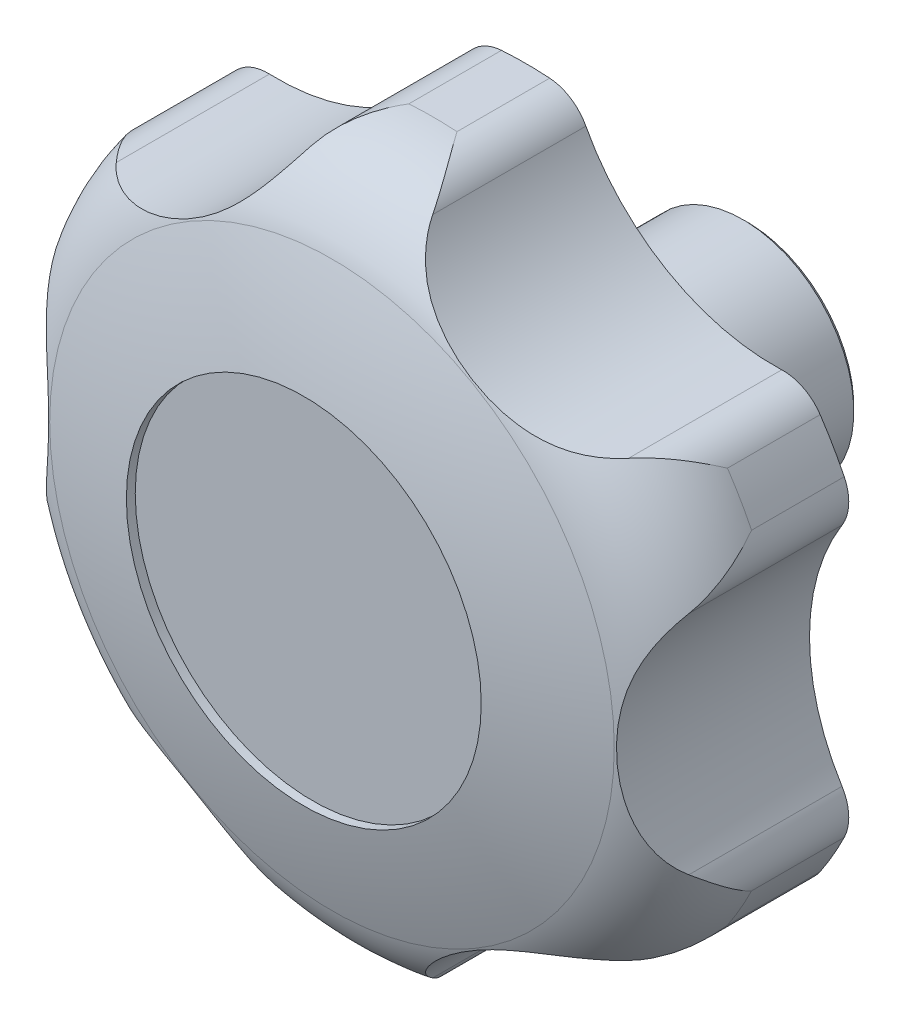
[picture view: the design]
ISO-10303-21;
HEADER;
FILE_DESCRIPTION(('STEP AP214'),'2;1');
FILE_NAME('part.step','',(''),(''),'','','');
FILE_SCHEMA(('AUTOMOTIVE_DESIGN { 1 0 10303 214 1 1 1 1 }'));
ENDSEC;
DATA;
#1=APPLICATION_CONTEXT('core data for automotive mechanical design processes');
#2=APPLICATION_PROTOCOL_DEFINITION('international standard','automotive_design',2000,#1);
#3=PRODUCT_CONTEXT('',#1,'mechanical');
#4=PRODUCT('Part','Part','',(#3));
#5=PRODUCT_RELATED_PRODUCT_CATEGORY('part','',(#4));
#6=PRODUCT_DEFINITION_FORMATION('','',#4);
#7=PRODUCT_DEFINITION_CONTEXT('part definition',#1,'design');
#8=PRODUCT_DEFINITION('design','',#6,#7);
#9=PRODUCT_DEFINITION_SHAPE('','',#8);
#10=(LENGTH_UNIT() NAMED_UNIT(*) SI_UNIT(.MILLI.,.METRE.));
#11=(NAMED_UNIT(*) PLANE_ANGLE_UNIT() SI_UNIT($,.RADIAN.));
#12=(NAMED_UNIT(*) SI_UNIT($,.STERADIAN.) SOLID_ANGLE_UNIT());
#13=UNCERTAINTY_MEASURE_WITH_UNIT(LENGTH_MEASURE(1.E-05),#10,'distance_accuracy_value','');
#14=(GEOMETRIC_REPRESENTATION_CONTEXT(3) GLOBAL_UNCERTAINTY_ASSIGNED_CONTEXT((#13)) GLOBAL_UNIT_ASSIGNED_CONTEXT((#10,
#11,#12)) REPRESENTATION_CONTEXT('',''));
#15=CARTESIAN_POINT('',(0.,0.,0.));
#16=DIRECTION('',(0.,0.,1.));
#17=DIRECTION('',(1.,0.,0.));
#18=AXIS2_PLACEMENT_3D('',#15,#16,#17);
#19=CARTESIAN_POINT('',(0.,0.,64.59576815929));
#20=DIRECTION('',(0.,0.,1.));
#21=DIRECTION('',(-1.,0.,0.));
#22=AXIS2_PLACEMENT_3D('',#19,#20,#21);
#23=CYLINDRICAL_SURFACE('',#22,40.);
#24=CARTESIAN_POINT('',(0.,0.,25.));
#25=DIRECTION('',(0.,0.,1.));
#26=DIRECTION('',(-1.,0.,0.));
#27=AXIS2_PLACEMENT_3D('',#24,#25,#26);
#28=CIRCLE('',#27,40.);
#29=CARTESIAN_POINT('',(33.2039586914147,-22.3046436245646,25.));
#30=VERTEX_POINT('',#29);
#31=CARTESIAN_POINT('',(35.9183673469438,-17.603149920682,25.));
#32=VERTEX_POINT('',#31);
#33=EDGE_CURVE('E457',#30,#32,#28,.T.);
#34=ORIENTED_EDGE('',*,*,#33,.T.);
#35=DIRECTION('',(0.,0.,1.));
#36=VECTOR('',#35,1.);
#37=CARTESIAN_POINT('',(35.9183673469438,-17.603149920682,0.));
#38=LINE('',#37,#36);
#39=CARTESIAN_POINT('',(35.9183673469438,-17.603149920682,35.4470247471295));
#40=VERTEX_POINT('',#39);
#41=EDGE_CURVE('E182',#32,#40,#38,.T.);
#42=ORIENTED_EDGE('',*,*,#41,.T.);
#43=CARTESIAN_POINT('',(0.,0.,35.4470247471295));
#44=DIRECTION('',(0.,0.,1.));
#45=DIRECTION('',(-1.,0.,0.));
#46=AXIS2_PLACEMENT_3D('',#43,#44,#45);
#47=CIRCLE('',#46,40.);
#48=CARTESIAN_POINT('',(33.2039586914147,-22.3046436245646,35.4470247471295));
#49=VERTEX_POINT('',#48);
#50=EDGE_CURVE('E198',#49,#40,#47,.T.);
#51=ORIENTED_EDGE('',*,*,#50,.F.);
#52=DIRECTION('',(0.,0.,1.));
#53=VECTOR('',#52,1.);
#54=CARTESIAN_POINT('',(33.2039586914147,-22.3046436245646,0.));
#55=LINE('',#54,#53);
#56=EDGE_CURVE('E526',#30,#49,#55,.T.);
#57=ORIENTED_EDGE('',*,*,#56,.F.);
#58=EDGE_LOOP('',(#34,#42,#51,#57));
#59=FACE_BOUND('',#58,.T.);
#60=ADVANCED_FACE('F14',(#59),#23,.T.);
#61=CARTESIAN_POINT('',(-2.71440865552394,-39.9077935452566,25.));
#62=VERTEX_POINT('',#61);
#63=CARTESIAN_POINT('',(2.71440865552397,-39.9077935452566,25.));
#64=VERTEX_POINT('',#63);
#65=EDGE_CURVE('E460',#62,#64,#28,.T.);
#66=ORIENTED_EDGE('',*,*,#65,.T.);
#67=DIRECTION('',(0.,0.,1.));
#68=VECTOR('',#67,1.);
#69=CARTESIAN_POINT('',(2.71440865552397,-39.9077935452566,0.));
#70=LINE('',#69,#68);
#71=CARTESIAN_POINT('',(2.71440865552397,-39.9077935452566,35.4470247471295));
#72=VERTEX_POINT('',#71);
#73=EDGE_CURVE('E532',#64,#72,#70,.T.);
#74=ORIENTED_EDGE('',*,*,#73,.T.);
#75=CARTESIAN_POINT('',(-2.71440865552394,-39.9077935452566,35.4470247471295));
#76=VERTEX_POINT('',#75);
#77=EDGE_CURVE('E474',#76,#72,#47,.T.);
#78=ORIENTED_EDGE('',*,*,#77,.F.);
#79=DIRECTION('',(0.,0.,1.));
#80=VECTOR('',#79,1.);
#81=CARTESIAN_POINT('',(-2.71440865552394,-39.9077935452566,0.));
#82=LINE('',#81,#80);
#83=EDGE_CURVE('E535',#62,#76,#82,.T.);
#84=ORIENTED_EDGE('',*,*,#83,.F.);
#85=EDGE_LOOP('',(#66,#74,#78,#84));
#86=FACE_BOUND('',#85,.T.);
#87=ADVANCED_FACE('F423',(#86),#23,.T.);
#88=CARTESIAN_POINT('',(-35.9183673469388,-17.603149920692,25.));
#89=VERTEX_POINT('',#88);
#90=CARTESIAN_POINT('',(-33.2039586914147,-22.3046436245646,25.));
#91=VERTEX_POINT('',#90);
#92=EDGE_CURVE('E463',#89,#91,#28,.T.);
#93=ORIENTED_EDGE('',*,*,#92,.T.);
#94=DIRECTION('',(0.,0.,1.));
#95=VECTOR('',#94,1.);
#96=CARTESIAN_POINT('',(-33.2039586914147,-22.3046436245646,0.));
#97=LINE('',#96,#95);
#98=CARTESIAN_POINT('',(-33.2039586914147,-22.3046436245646,35.4470247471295));
#99=VERTEX_POINT('',#98);
#100=EDGE_CURVE('E543',#91,#99,#97,.T.);
#101=ORIENTED_EDGE('',*,*,#100,.T.);
#102=CARTESIAN_POINT('',(-35.9183673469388,-17.603149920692,35.4470247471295));
#103=VERTEX_POINT('',#102);
#104=EDGE_CURVE('E470',#103,#99,#47,.T.);
#105=ORIENTED_EDGE('',*,*,#104,.F.);
#106=DIRECTION('',(0.,0.,1.));
#107=VECTOR('',#106,1.);
#108=CARTESIAN_POINT('',(-35.9183673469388,-17.603149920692,0.));
#109=LINE('',#108,#107);
#110=EDGE_CURVE('E546',#89,#103,#109,.T.);
#111=ORIENTED_EDGE('',*,*,#110,.F.);
#112=EDGE_LOOP('',(#93,#101,#105,#111));
#113=FACE_BOUND('',#112,.T.);
#114=ADVANCED_FACE('F431',(#113),#23,.T.);
#115=CARTESIAN_POINT('',(-33.2039586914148,22.3046436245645,25.));
#116=VERTEX_POINT('',#115);
#117=CARTESIAN_POINT('',(-35.9183673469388,17.603149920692,25.));
#118=VERTEX_POINT('',#117);
#119=EDGE_CURVE('E462',#116,#118,#28,.T.);
#120=ORIENTED_EDGE('',*,*,#119,.T.);
#121=DIRECTION('',(0.,0.,1.));
#122=VECTOR('',#121,1.);
#123=CARTESIAN_POINT('',(-35.9183673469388,17.603149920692,0.));
#124=LINE('',#123,#122);
#125=CARTESIAN_POINT('',(-35.9183673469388,17.603149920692,35.4470247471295));
#126=VERTEX_POINT('',#125);
#127=EDGE_CURVE('E37',#118,#126,#124,.T.);
#128=ORIENTED_EDGE('',*,*,#127,.T.);
#129=CARTESIAN_POINT('',(-33.2039586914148,22.3046436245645,35.4470247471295));
#130=VERTEX_POINT('',#129);
#131=EDGE_CURVE('E467',#130,#126,#47,.T.);
#132=ORIENTED_EDGE('',*,*,#131,.F.);
#133=DIRECTION('',(0.,0.,1.));
#134=VECTOR('',#133,1.);
#135=CARTESIAN_POINT('',(-33.2039586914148,22.3046436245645,0.));
#136=LINE('',#135,#134);
#137=EDGE_CURVE('E555',#116,#130,#136,.T.);
#138=ORIENTED_EDGE('',*,*,#137,.F.);
#139=EDGE_LOOP('',(#120,#128,#132,#138));
#140=FACE_BOUND('',#139,.T.);
#141=ADVANCED_FACE('F444',(#140),#23,.T.);
#142=CARTESIAN_POINT('',(2.71440865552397,39.9077935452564,25.));
#143=VERTEX_POINT('',#142);
#144=CARTESIAN_POINT('',(-2.714408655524,39.9077935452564,25.));
#145=VERTEX_POINT('',#144);
#146=EDGE_CURVE('E458',#143,#145,#28,.T.);
#147=ORIENTED_EDGE('',*,*,#146,.T.);
#148=DIRECTION('',(0.,0.,1.));
#149=VECTOR('',#148,1.);
#150=CARTESIAN_POINT('',(-2.714408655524,39.9077935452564,0.));
#151=LINE('',#150,#149);
#152=CARTESIAN_POINT('',(-2.714408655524,39.9077935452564,35.4470247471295));
#153=VERTEX_POINT('',#152);
#154=EDGE_CURVE('E563',#145,#153,#151,.T.);
#155=ORIENTED_EDGE('',*,*,#154,.T.);
#156=CARTESIAN_POINT('',(2.71440865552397,39.9077935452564,35.4470247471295));
#157=VERTEX_POINT('',#156);
#158=EDGE_CURVE('E876',#157,#153,#47,.T.);
#159=ORIENTED_EDGE('',*,*,#158,.F.);
#160=DIRECTION('',(0.,0.,1.));
#161=VECTOR('',#160,1.);
#162=CARTESIAN_POINT('',(2.71440865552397,39.9077935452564,0.));
#163=LINE('',#162,#161);
#164=EDGE_CURVE('E566',#143,#157,#163,.T.);
#165=ORIENTED_EDGE('',*,*,#164,.F.);
#166=EDGE_LOOP('',(#147,#155,#159,#165));
#167=FACE_BOUND('',#166,.T.);
#168=ADVANCED_FACE('F435',(#167),#23,.T.);
#169=CARTESIAN_POINT('',(35.9183673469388,17.603149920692,25.));
#170=VERTEX_POINT('',#169);
#171=CARTESIAN_POINT('',(33.2039586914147,22.3046436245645,25.));
#172=VERTEX_POINT('',#171);
#173=EDGE_CURVE('E450',#170,#172,#28,.T.);
#174=ORIENTED_EDGE('',*,*,#173,.T.);
#175=DIRECTION('',(0.,0.,1.));
#176=VECTOR('',#175,1.);
#177=CARTESIAN_POINT('',(33.2039586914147,22.3046436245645,0.));
#178=LINE('',#177,#176);
#179=CARTESIAN_POINT('',(33.2039586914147,22.3046436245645,35.4470247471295));
#180=VERTEX_POINT('',#179);
#181=EDGE_CURVE('E452',#172,#180,#178,.T.);
#182=ORIENTED_EDGE('',*,*,#181,.T.);
#183=CARTESIAN_POINT('',(35.9183673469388,17.603149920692,35.4470247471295));
#184=VERTEX_POINT('',#183);
#185=EDGE_CURVE('E883',#184,#180,#47,.T.);
#186=ORIENTED_EDGE('',*,*,#185,.F.);
#187=DIRECTION('',(0.,0.,1.));
#188=VECTOR('',#187,1.);
#189=CARTESIAN_POINT('',(35.9183673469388,17.603149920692,0.));
#190=LINE('',#189,#188);
#191=EDGE_CURVE('E454',#170,#184,#190,.T.);
#192=ORIENTED_EDGE('',*,*,#191,.F.);
#193=EDGE_LOOP('',(#174,#182,#186,#192));
#194=FACE_BOUND('',#193,.T.);
#195=ADVANCED_FACE('F425',(#194),#23,.T.);
#196=CARTESIAN_POINT('',(0.,0.,0.));
#197=DIRECTION('',(0.,0.,1.));
#198=DIRECTION('',(-1.,0.,0.));
#199=AXIS2_PLACEMENT_3D('',#196,#197,#198);
#200=CONICAL_SURFACE('',#199,12.,0.785398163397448);
#201=CARTESIAN_POINT('',(0.,0.,0.5));
#202=DIRECTION('',(0.,0.,1.));
#203=DIRECTION('',(-1.,0.,0.));
#204=AXIS2_PLACEMENT_3D('',#201,#202,#203);
#205=CIRCLE('',#204,12.5);
#206=CARTESIAN_POINT('',(-12.5,0.,0.5));
#207=VERTEX_POINT('',#206);
#208=EDGE_CURVE('E856',#207,#207,#205,.T.);
#209=ORIENTED_EDGE('',*,*,#208,.F.);
#210=EDGE_LOOP('',(#209));
#211=FACE_BOUND('',#210,.T.);
#212=CARTESIAN_POINT('',(0.,0.,0.));
#213=DIRECTION('',(0.,0.,1.));
#214=DIRECTION('',(-1.,0.,0.));
#215=AXIS2_PLACEMENT_3D('',#212,#213,#214);
#216=CIRCLE('',#215,12.);
#217=CARTESIAN_POINT('',(-12.,0.,0.));
#218=VERTEX_POINT('',#217);
#219=EDGE_CURVE('E477',#218,#218,#216,.T.);
#220=ORIENTED_EDGE('',*,*,#219,.T.);
#221=EDGE_LOOP('',(#220));
#222=FACE_BOUND('',#221,.T.);
#223=ADVANCED_FACE('F16',(#211,#222),#200,.T.);
#224=CARTESIAN_POINT('',(0.,-1.94289029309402E-13,0.));
#225=DIRECTION('',(0.,0.,1.));
#226=DIRECTION('',(-1.,0.,0.));
#227=AXIS2_PLACEMENT_3D('',#224,#225,#226);
#228=PLANE('',#227);
#229=CARTESIAN_POINT('',(0.,0.,0.));
#230=DIRECTION('',(0.,0.,-1.));
#231=DIRECTION('',(1.,0.,0.));
#232=AXIS2_PLACEMENT_3D('',#229,#230,#231);
#233=CIRCLE('',#232,8.);
#234=CARTESIAN_POINT('',(8.,0.,0.));
#235=VERTEX_POINT('',#234);
#236=EDGE_CURVE('E579',#235,#235,#233,.T.);
#237=ORIENTED_EDGE('',*,*,#236,.F.);
#238=EDGE_LOOP('',(#237));
#239=FACE_BOUND('',#238,.T.);
#240=ORIENTED_EDGE('',*,*,#219,.F.);
#241=EDGE_LOOP('',(#240));
#242=FACE_BOUND('',#241,.T.);
#243=ADVANCED_FACE('F442',(#239,#242),#228,.F.);
#244=CARTESIAN_POINT('',(0.,0.,-47.979589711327));
#245=DIRECTION('',(-1.,0.,0.));
#246=DIRECTION('',(0.,0.,-1.));
#247=AXIS2_PLACEMENT_3D('',#244,#245,#246);
#248=SPHERICAL_SURFACE('',#247,100.);
#249=CARTESIAN_POINT('',(0.,0.,-47.979589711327));
#250=DIRECTION('',(0.,0.,1.));
#251=DIRECTION('',(-1.,0.,0.));
#252=AXIS2_PLACEMENT_3D('',#249,#250,#251);
#253=SPHERICAL_SURFACE('',#252,100.);
#254=CARTESIAN_POINT('',(0.,0.,46.823381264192));
#255=DIRECTION('',(0.,0.,1.));
#256=DIRECTION('',(-1.,0.,0.));
#257=AXIS2_PLACEMENT_3D('',#254,#255,#256);
#258=CIRCLE('',#257,31.8181818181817);
#259=CARTESIAN_POINT('',(-31.8181818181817,0.,46.823381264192));
#260=VERTEX_POINT('',#259);
#261=EDGE_CURVE('E473',#260,#260,#258,.T.);
#262=ORIENTED_EDGE('',*,*,#261,.T.);
#263=EDGE_LOOP('',(#262));
#264=FACE_BOUND('',#263,.T.);
#265=CARTESIAN_POINT('',(0.,0.,50.));
#266=DIRECTION('',(0.,0.,1.));
#267=DIRECTION('',(-1.,0.,0.));
#268=AXIS2_PLACEMENT_3D('',#265,#266,#267);
#269=CIRCLE('',#268,20.);
#270=CARTESIAN_POINT('',(-20.,0.,50.));
#271=VERTEX_POINT('',#270);
#272=EDGE_CURVE('E199',#271,#271,#269,.T.);
#273=ORIENTED_EDGE('',*,*,#272,.F.);
#274=EDGE_LOOP('',(#273));
#275=FACE_BOUND('',#274,.T.);
#276=ADVANCED_FACE('F586',(#264,#275),#253,.T.);
#277=CARTESIAN_POINT('',(0.,0.,35.44702474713));
#278=DIRECTION('',(0.,0.,1.));
#279=DIRECTION('',(-1.,0.,0.));
#280=AXIS2_PLACEMENT_3D('',#277,#278,#279);
#281=TOROIDAL_SURFACE('',#280,28.,12.);
#282=CARTESIAN_POINT('',(33.2039586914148,-22.3046436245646,35.44702474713));
#283=CARTESIAN_POINT('',(33.2016458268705,-22.3080866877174,35.4530354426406));
#284=CARTESIAN_POINT('',(33.1993286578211,-22.3115269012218,35.4590461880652));
#285=CARTESIAN_POINT('',(33.0621842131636,-22.5145941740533,35.8141433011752));
#286=CARTESIAN_POINT('',(32.9128604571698,-22.7045847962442,36.1633854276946));
#287=CARTESIAN_POINT('',(32.5872275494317,-23.062127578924,36.860845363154));
#288=CARTESIAN_POINT('',(32.4109089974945,-23.2296718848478,37.2090627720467));
#289=CARTESIAN_POINT('',(32.0328927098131,-23.5393466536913,37.9038529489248));
#290=CARTESIAN_POINT('',(31.8311572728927,-23.6814385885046,38.2504224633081));
#291=CARTESIAN_POINT('',(31.4045582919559,-23.9362981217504,38.9399718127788));
#292=CARTESIAN_POINT('',(31.1797053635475,-24.0490790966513,39.2829532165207));
#293=CARTESIAN_POINT('',(30.7879651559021,-24.2091174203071,39.8497011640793));
#294=CARTESIAN_POINT('',(30.6268988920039,-24.2656677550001,40.0749071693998));
#295=CARTESIAN_POINT('',(30.2963113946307,-24.3626945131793,40.5224669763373));
#296=CARTESIAN_POINT('',(30.1267933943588,-24.4031770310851,40.744821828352));
#297=CARTESIAN_POINT('',(29.7801340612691,-24.466615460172,41.1860795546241));
#298=CARTESIAN_POINT('',(29.6029933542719,-24.4895728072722,41.4049827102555));
#299=CARTESIAN_POINT('',(29.2420201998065,-24.5162777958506,41.8387209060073));
#300=CARTESIAN_POINT('',(29.0581817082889,-24.5200076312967,42.0535519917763));
#301=CARTESIAN_POINT('',(28.8716321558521,-24.5132558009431,42.2658258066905));
#302=B_SPLINE_CURVE_WITH_KNOTS('',3,(#282,#283,#284,#285,#286,#287,#288,#289,#290,#291,#292,
#293,#294,#295,#296,#297,#298,#299,#300,#301),.UNSPECIFIED.,.F.,.F.,(4,2,2,2,2,2,2,2,2,4),(0.,
0.0219089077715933,1.29430371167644,2.5671426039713,3.84189224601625,5.11605911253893,
5.96330602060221,6.8102312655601,7.65708711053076,8.50472706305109),.UNSPECIFIED.);
#303=CARTESIAN_POINT('',(28.8718321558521,-24.5132630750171,42.2655982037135));
#304=VERTEX_POINT('',#303);
#305=EDGE_CURVE('E200',#49,#304,#302,.T.);
#306=ORIENTED_EDGE('',*,*,#305,.F.);
#307=ORIENTED_EDGE('',*,*,#50,.T.);
#308=CARTESIAN_POINT('',(35.6648992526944,-12.7469085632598,42.2658666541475));
#309=CARTESIAN_POINT('',(35.7234532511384,-12.8403174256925,42.1404930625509));
#310=CARTESIAN_POINT('',(35.7783600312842,-12.9347527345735,42.0142254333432));
#311=CARTESIAN_POINT('',(35.8810719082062,-13.1252663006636,41.7600922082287));
#312=CARTESIAN_POINT('',(35.9288784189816,-13.2213442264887,41.6322269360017));
#313=CARTESIAN_POINT('',(36.0618532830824,-13.5112308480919,41.2467805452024));
#314=CARTESIAN_POINT('',(36.1367290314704,-13.7069387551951,40.9870200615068));
#315=CARTESIAN_POINT('',(36.2603267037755,-14.1002303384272,40.4635033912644));
#316=CARTESIAN_POINT('',(36.3090884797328,-14.2978106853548,40.1997539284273));
#317=CARTESIAN_POINT('',(36.3820057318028,-14.6929287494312,39.6687368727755));
#318=CARTESIAN_POINT('',(36.4061527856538,-14.8904664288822,39.4014681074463));
#319=CARTESIAN_POINT('',(36.4325564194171,-15.3076554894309,38.8311912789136));
#320=CARTESIAN_POINT('',(36.4317470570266,-15.5270305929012,38.5278395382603));
#321=CARTESIAN_POINT('',(36.4021049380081,-15.9605923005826,37.9187847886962));
#322=CARTESIAN_POINT('',(36.3732684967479,-16.1747782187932,37.6130814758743));
#323=CARTESIAN_POINT('',(36.2889979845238,-16.5953080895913,37.0006549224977));
#324=CARTESIAN_POINT('',(36.2336026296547,-16.8016629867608,36.6939338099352));
#325=CARTESIAN_POINT('',(36.0974410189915,-17.2046623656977,36.079792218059));
#326=CARTESIAN_POINT('',(36.0166818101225,-17.4013095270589,35.7723719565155));
#327=CARTESIAN_POINT('',(35.9220134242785,-17.5956985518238,35.4590461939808));
#328=CARTESIAN_POINT('',(35.9201926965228,-17.5994253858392,35.453035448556));
#329=CARTESIAN_POINT('',(35.9183673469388,-17.603149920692,35.44702474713));
#330=B_SPLINE_CURVE_WITH_KNOTS('',3,(#308,#309,#310,#311,#312,#313,#314,#315,#316,#317,#318,
#319,#320,#321,#322,#323,#324,#325,#326,#327,#328,#329),.UNSPECIFIED.,.F.,.F.,(4,2,2,2,2,2,2,2,
2,2,4),(0.,0.50074643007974,1.0013930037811,2.0013764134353,2.99982938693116,3.99862388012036,
5.12056047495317,6.24264458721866,7.36309793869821,8.48324026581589,8.50514917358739),.UNSPECIFIED.);
#331=CARTESIAN_POINT('',(35.6650246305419,-12.7471085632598,42.2655982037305));
#332=VERTEX_POINT('',#331);
#333=EDGE_CURVE('E186',#332,#40,#330,.T.);
#334=ORIENTED_EDGE('',*,*,#333,.F.);
#335=CARTESIAN_POINT('',(35.6651500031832,-12.7473085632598,42.2653297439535));
#336=CARTESIAN_POINT('',(35.6085788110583,-12.657064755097,42.3864729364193));
#337=CARTESIAN_POINT('',(35.5511259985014,-12.5640789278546,42.505127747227));
#338=CARTESIAN_POINT('',(35.4348010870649,-12.372757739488,42.7373042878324));
#339=CARTESIAN_POINT('',(35.3759290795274,-12.2744227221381,42.8508263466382));
#340=CARTESIAN_POINT('',(35.1978187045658,-11.9717980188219,43.183239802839));
#341=CARTESIAN_POINT('',(35.0769610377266,-11.759691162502,43.3942434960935));
#342=CARTESIAN_POINT('',(34.8351019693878,-11.3185575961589,43.7921481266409));
#343=CARTESIAN_POINT('',(34.7141137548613,-11.0897185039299,43.9792663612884));
#344=CARTESIAN_POINT('',(34.4734853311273,-10.6150811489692,44.3316300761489));
#345=CARTESIAN_POINT('',(34.3538453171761,-10.3692804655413,44.4968724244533));
#346=CARTESIAN_POINT('',(34.118747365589,-9.86348535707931,44.8053655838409));
#347=CARTESIAN_POINT('',(34.003278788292,-9.60353201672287,44.9486758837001));
#348=CARTESIAN_POINT('',(33.7783302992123,-9.0708864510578,45.2147402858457));
#349=CARTESIAN_POINT('',(33.6688502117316,-8.79819459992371,45.3374949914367));
#350=CARTESIAN_POINT('',(33.4574270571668,-8.2414359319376,45.5640287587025));
#351=CARTESIAN_POINT('',(33.355501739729,-7.95734460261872,45.6677639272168));
#352=CARTESIAN_POINT('',(33.1608918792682,-7.3802416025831,45.8575354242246));
#353=CARTESIAN_POINT('',(33.0682085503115,-7.08722876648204,45.9435694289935));
#354=CARTESIAN_POINT('',(32.8468004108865,-6.33664057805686,46.1411058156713));
#355=CARTESIAN_POINT('',(32.7250175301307,-5.87417592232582,46.2419297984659));
#356=CARTESIAN_POINT('',(32.5084193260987,-4.93732591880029,46.4126100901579));
#357=CARTESIAN_POINT('',(32.4136174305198,-4.46293476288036,46.4824509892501));
#358=CARTESIAN_POINT('',(32.2523910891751,-3.50533052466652,46.5968256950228));
#359=CARTESIAN_POINT('',(32.1860288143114,-3.02210049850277,46.6413041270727));
#360=CARTESIAN_POINT('',(32.0828256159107,-2.05113738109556,46.7089202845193));
#361=CARTESIAN_POINT('',(32.0459807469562,-1.56340490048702,46.7320608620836));
#362=CARTESIAN_POINT('',(32.0014874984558,-0.570823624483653,46.7598837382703));
#363=CARTESIAN_POINT('',(31.9947863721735,-0.0659157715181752,46.7639673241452));
#364=CARTESIAN_POINT('',(32.0132306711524,0.943168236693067,46.7525345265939));
#365=CARTESIAN_POINT('',(32.0383802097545,1.44734428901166,46.7370156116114));
#366=CARTESIAN_POINT('',(32.1202170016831,2.45139648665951,46.6846206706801));
#367=CARTESIAN_POINT('',(32.1768642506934,2.95127727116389,46.647771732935));
#368=CARTESIAN_POINT('',(32.3209795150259,3.94402208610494,46.5488585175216));
#369=CARTESIAN_POINT('',(32.4084384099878,4.43688814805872,46.4868017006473));
#370=CARTESIAN_POINT('',(32.5883264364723,5.29501706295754,46.3503630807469));
#371=CARTESIAN_POINT('',(32.6745687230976,5.66261664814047,46.2824745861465));
#372=CARTESIAN_POINT('',(32.8630501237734,6.38923539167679,46.1258564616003));
#373=CARTESIAN_POINT('',(32.9652885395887,6.74825492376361,46.0371277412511));
#374=CARTESIAN_POINT('',(33.1840934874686,7.45459097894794,45.8358574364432));
#375=CARTESIAN_POINT('',(33.3006411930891,7.80192212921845,45.7233470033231));
#376=CARTESIAN_POINT('',(33.5459960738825,8.48223685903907,45.4714791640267));
#377=CARTESIAN_POINT('',(33.6748001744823,8.81522400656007,45.3321284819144));
#378=CARTESIAN_POINT('',(33.9165908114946,9.40234329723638,45.0531451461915));
#379=CARTESIAN_POINT('',(34.0279848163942,9.65951147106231,44.9185129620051));
#380=CARTESIAN_POINT('',(34.2549904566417,10.1602198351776,44.6290220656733));
#381=CARTESIAN_POINT('',(34.3706011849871,10.4037629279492,44.474167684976));
#382=CARTESIAN_POINT('',(34.6036653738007,10.8750119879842,44.1439922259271));
#383=CARTESIAN_POINT('',(34.7211158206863,11.1027410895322,43.9687020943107));
#384=CARTESIAN_POINT('',(34.9555495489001,11.5409190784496,43.5975963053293));
#385=CARTESIAN_POINT('',(35.0725330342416,11.7513765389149,43.4017909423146));
#386=CARTESIAN_POINT('',(35.2696517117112,12.0946088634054,43.0505692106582));
#387=CARTESIAN_POINT('',(35.3505397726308,12.2320760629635,42.9001303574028));
#388=CARTESIAN_POINT('',(35.509879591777,12.4971557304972,42.5897662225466));
#389=CARTESIAN_POINT('',(35.5883327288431,12.6247738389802,42.4298464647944));
#390=CARTESIAN_POINT('',(35.6651500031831,12.7473085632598,42.2653297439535));
#391=B_SPLINE_CURVE_WITH_KNOTS('',3,(#335,#336,#337,#338,#339,#340,#341,#342,#343,#344,#345,
#346,#347,#348,#349,#350,#351,#352,#353,#354,#355,#356,#357,#358,#359,#360,#361,#362,#363,#364,
#365,#366,#367,#368,#369,#370,#371,#372,#373,#374,#375,#376,#377,#378,#379,#380,#381,#382,#383,
#384,#385,#386,#387,#388,#389,#390),.UNSPECIFIED.,.F.,.F.,(4,2,2,2,2,2,2,2,2,2,2,2,2,2,2,2,2,2,
2,2,2,2,2,2,2,2,2,4),(0.,0.483826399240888,0.967621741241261,1.93415653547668,2.89115364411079,
3.84828761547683,4.80277758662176,5.75723953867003,6.71387720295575,7.67064037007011,
9.13462899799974,10.5993449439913,12.0672467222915,13.5349522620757,15.0484714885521,
16.5621861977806,18.0739827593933,19.5853321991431,20.7353651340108,21.8853478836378,
23.03383351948,24.1820318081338,25.1138844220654,26.0455377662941,26.9757981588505,
27.905593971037,28.5629371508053,29.2199010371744),.UNSPECIFIED.);
#392=CARTESIAN_POINT('',(35.6650246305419,12.7471085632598,42.2655982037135));
#393=VERTEX_POINT('',#392);
#394=EDGE_CURVE('E174',#332,#393,#391,.T.);
#395=ORIENTED_EDGE('',*,*,#394,.T.);
#396=CARTESIAN_POINT('',(35.9183673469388,17.603149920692,35.44702474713));
#397=CARTESIAN_POINT('',(35.9201926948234,17.5994253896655,35.4530354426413));
#398=CARTESIAN_POINT('',(35.9220134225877,17.5956985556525,35.4590461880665));
#399=CARTESIAN_POINT('',(36.0293026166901,17.375394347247,35.8141432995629));
#400=CARTESIAN_POINT('',(36.1191774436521,17.1510808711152,36.1633854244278));
#401=CARTESIAN_POINT('',(36.2660021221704,16.6903031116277,36.8608453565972));
#402=CARTESIAN_POINT('',(36.322940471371,16.4538346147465,37.2090627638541));
#403=CARTESIAN_POINT('',(36.4021185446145,15.9716255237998,37.9038529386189));
#404=CARTESIAN_POINT('',(36.4243060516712,15.7258715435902,38.2504224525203));
#405=CARTESIAN_POINT('',(36.4317213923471,15.2289962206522,38.9399718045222));
#406=CARTESIAN_POINT('',(36.4169661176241,14.977877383,39.2829532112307));
#407=CARTESIAN_POINT('',(36.3596929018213,14.5585985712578,39.8497047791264));
#408=CARTESIAN_POINT('',(36.3281331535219,14.390833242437,40.0749143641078));
#409=CARTESIAN_POINT('',(36.2468651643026,14.0560173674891,40.5224812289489));
#410=CARTESIAN_POINT('',(36.1971638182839,13.8889665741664,40.7448395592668));
#411=CARTESIAN_POINT('',(36.0787703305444,13.5570263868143,41.1861041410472));
#412=CARTESIAN_POINT('',(36.0100797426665,13.3921368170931,41.4050106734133));
#413=CARTESIAN_POINT('',(35.8527159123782,13.0661675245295,41.8387554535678));
#414=CARTESIAN_POINT('',(35.764024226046,12.9050914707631,42.0535897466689));
#415=CARTESIAN_POINT('',(35.6648992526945,12.7469085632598,42.2658666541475));
#416=B_SPLINE_CURVE_WITH_KNOTS('',3,(#396,#397,#398,#399,#400,#401,#402,#403,#404,#405,#406,
#407,#408,#409,#410,#411,#412,#413,#414,#415),.UNSPECIFIED.,.F.,.F.,(4,2,2,2,2,2,2,2,2,4),(0.,
0.0219089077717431,1.29430370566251,2.56714259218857,3.84189223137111,5.11605911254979,
5.96331954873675,6.81025830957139,7.6571277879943,8.50478141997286),.UNSPECIFIED.);
#417=EDGE_CURVE('E181',#184,#393,#416,.T.);
#418=ORIENTED_EDGE('',*,*,#417,.F.);
#419=ORIENTED_EDGE('',*,*,#185,.T.);
#420=CARTESIAN_POINT('',(28.8716321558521,24.5132558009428,42.2658258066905));
#421=CARTESIAN_POINT('',(28.9818038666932,24.5172598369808,42.1404514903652));
#422=CARTESIAN_POINT('',(29.0910408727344,24.5175920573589,42.0141831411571));
#423=CARTESIAN_POINT('',(29.3073868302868,24.5112847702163,41.7600484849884));
#424=CARTESIAN_POINT('',(29.4144962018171,24.5046466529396,41.6321825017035));
#425=CARTESIAN_POINT('',(29.7320333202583,24.4748605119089,41.2467339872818));
#426=CARTESIAN_POINT('',(29.9389594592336,24.4418492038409,40.9869721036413));
#427=CARTESIAN_POINT('',(30.34135909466,24.3522387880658,40.4634526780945));
#428=CARTESIAN_POINT('',(30.5368496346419,24.2956758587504,40.1997018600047));
#429=CARTESIAN_POINT('',(30.9154904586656,24.1612616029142,39.6686821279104));
#430=CARTESIAN_POINT('',(31.098636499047,24.083403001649,39.4014120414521));
#431=CARTESIAN_POINT('',(31.4731301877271,23.8976729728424,38.8311384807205));
#432=CARTESIAN_POINT('',(31.6627059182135,23.7872849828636,38.5277913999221));
#433=CARTESIAN_POINT('',(32.0233528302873,23.5448350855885,37.9187460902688));
#434=CARTESIAN_POINT('',(32.1944215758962,23.4127703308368,37.6130475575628));
#435=CARTESIAN_POINT('',(32.5164695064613,23.1295282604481,37.0006306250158));
#436=CARTESIAN_POINT('',(32.6674775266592,22.9783790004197,36.6939143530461));
#437=CARTESIAN_POINT('',(32.948399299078,22.6589644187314,36.079782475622));
#438=CARTESIAN_POINT('',(33.0783188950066,22.4907038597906,35.7723670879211));
#439=CARTESIAN_POINT('',(33.1993286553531,22.3115269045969,35.4590461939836));
#440=CARTESIAN_POINT('',(33.2016458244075,22.3080866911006,35.4530354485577));
#441=CARTESIAN_POINT('',(33.2039586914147,22.3046436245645,35.44702474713));
#442=B_SPLINE_CURVE_WITH_KNOTS('',3,(#420,#421,#422,#423,#424,#425,#426,#427,#428,#429,#430,
#431,#432,#433,#434,#435,#436,#437,#438,#439,#440,#441),.UNSPECIFIED.,.F.,.F.,(4,2,2,2,2,2,2,2,
2,2,4),(0.,0.500748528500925,1.00139720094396,2.00138482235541,2.99984196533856,3.9986406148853,
5.12055943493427,6.24262574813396,7.36306133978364,8.48318592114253,8.50509482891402),.UNSPECIFIED.);
#443=CARTESIAN_POINT('',(28.8718321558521,24.5132630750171,42.2655982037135));
#444=VERTEX_POINT('',#443);
#445=EDGE_CURVE('E250',#444,#180,#442,.T.);
#446=ORIENTED_EDGE('',*,*,#445,.F.);
#447=CARTESIAN_POINT('',(28.8720321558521,24.5132703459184,42.265370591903));
#448=CARTESIAN_POINT('',(28.7655922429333,24.509400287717,42.3865135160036));
#449=CARTESIAN_POINT('',(28.6563368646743,24.506137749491,42.505168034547));
#450=CARTESIAN_POINT('',(28.432483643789,24.5010583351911,42.7373439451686));
#451=CARTESIAN_POINT('',(28.3178861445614,24.4992413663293,42.8508656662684));
#452=CARTESIAN_POINT('',(27.9667476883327,24.4963061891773,43.1832780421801));
#453=CARTESIAN_POINT('',(27.7226272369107,24.4976942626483,43.3942809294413));
#454=CARTESIAN_POINT('',(27.2196615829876,24.5088059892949,43.7921837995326));
#455=CARTESIAN_POINT('',(26.9609854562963,24.5184472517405,43.9793010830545));
#456=CARTESIAN_POINT('',(26.4296202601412,24.5473768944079,44.3316628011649));
#457=CARTESIAN_POINT('',(26.1569291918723,24.5666666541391,44.4969041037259));
#458=CARTESIAN_POINT('',(25.6013461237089,24.6159649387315,44.8053951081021));
#459=CARTESIAN_POINT('',(25.3184843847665,24.6459437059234,44.9487043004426));
#460=CARTESIAN_POINT('',(24.7447231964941,24.7174571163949,45.2147664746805));
#461=CARTESIAN_POINT('',(24.4538239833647,24.7589914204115,45.3375200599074));
#462=CARTESIAN_POINT('',(23.8659431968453,24.8542748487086,45.5640516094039));
#463=CARTESIAN_POINT('',(23.5689492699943,24.9080516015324,45.6677856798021));
#464=CARTESIAN_POINT('',(22.9718567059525,25.0280680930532,45.8575550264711));
#465=CARTESIAN_POINT('',(22.6717576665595,25.0943094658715,45.9435879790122));
#466=CARTESIAN_POINT('',(21.9110220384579,25.2778615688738,46.1411221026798));
#467=CARTESIAN_POINT('',(21.4496222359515,25.4036289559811,46.2419448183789));
#468=CARTESIAN_POINT('',(20.5299830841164,25.6844789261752,46.4126226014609));
#469=CARTESIAN_POINT('',(20.0717454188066,25.8395760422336,46.482462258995));
#470=CARTESIAN_POINT('',(19.1618190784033,26.1787570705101,46.5968345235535));
#471=CARTESIAN_POINT('',(18.710146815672,26.3629032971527,46.6413117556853));
#472=CARTESIAN_POINT('',(17.8176634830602,26.7590137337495,46.7089255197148));
#473=CARTESIAN_POINT('',(17.3768509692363,26.9709742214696,46.7320649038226));
#474=CARTESIAN_POINT('',(16.4950014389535,27.4287384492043,46.7598852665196));
#475=CARTESIAN_POINT('',(16.0543869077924,27.6753920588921,46.7639675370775));
#476=CARTESIAN_POINT('',(15.1897151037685,28.1959134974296,46.7525318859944));
#477=CARTESIAN_POINT('',(14.7656599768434,28.4697848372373,46.7370114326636));
#478=CARTESIAN_POINT('',(13.9370427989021,29.0426900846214,46.684613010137));
#479=CARTESIAN_POINT('',(13.5324567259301,29.3416916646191,46.6477621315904));
#480=CARTESIAN_POINT('',(12.7447720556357,29.9628780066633,46.5488444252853));
#481=CARTESIAN_POINT('',(12.3616671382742,30.2850558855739,46.4867850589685));
#482=CARTESIAN_POINT('',(11.7084538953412,30.8699103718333,46.3503419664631));
#483=CARTESIAN_POINT('',(11.4332282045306,31.128397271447,46.2824519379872));
#484=CARTESIAN_POINT('',(10.8982060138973,31.6549341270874,46.1258307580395));
#485=CARTESIAN_POINT('',(10.6384088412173,31.9229836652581,46.0371005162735));
#486=CARTESIAN_POINT('',(10.1361135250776,32.4656393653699,45.8358272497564));
#487=CARTESIAN_POINT('',(9.89359330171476,32.7402365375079,45.723315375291));
#488=CARTESIAN_POINT('',(9.42710779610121,33.2928737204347,45.4714448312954));
#489=CARTESIAN_POINT('',(9.2031378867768,33.5709128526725,45.3320928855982));
#490=CARTESIAN_POINT('',(8.81557789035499,34.0738665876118,45.0531067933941));
#491=CARTESIAN_POINT('',(8.64856236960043,34.2989200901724,44.9184729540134));
#492=CARTESIAN_POINT('',(8.32844232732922,34.7458654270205,44.6289787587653));
#493=CARTESIAN_POINT('',(8.17533483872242,34.9677579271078,44.4741227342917));
#494=CARTESIAN_POINT('',(7.88375656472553,35.4052199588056,44.1439440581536));
#495=CARTESIAN_POINT('',(7.7452642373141,35.6207984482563,43.9686523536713));
#496=CARTESIAN_POINT('',(7.48301106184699,36.0429105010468,43.5975435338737));
#497=CARTESIAN_POINT('',(7.35924289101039,36.2494485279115,43.4017367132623));
#498=CARTESIAN_POINT('',(7.1605629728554,36.5917616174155,43.0505232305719));
#499=CARTESIAN_POINT('',(7.08196345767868,36.7305353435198,42.9000947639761));
#500=CARTESIAN_POINT('',(6.93207963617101,37.0010465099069,42.5897528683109));
#501=CARTESIAN_POINT('',(6.86079113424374,37.1327879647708,42.4298449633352));
#502=CARTESIAN_POINT('',(6.79308650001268,37.2605716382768,42.2653407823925));
#503=B_SPLINE_CURVE_WITH_KNOTS('',3,(#447,#448,#449,#450,#451,#452,#453,#454,#455,#456,#457,
#458,#459,#460,#461,#462,#463,#464,#465,#466,#467,#468,#469,#470,#471,#472,#473,#474,#475,#476,
#477,#478,#479,#480,#481,#482,#483,#484,#485,#486,#487,#488,#489,#490,#491,#492,#493,#494,#495,
#496,#497,#498,#499,#500,#501,#502),.UNSPECIFIED.,.F.,.F.,(4,2,2,2,2,2,2,2,2,2,2,2,2,2,2,2,2,2,
2,2,2,2,2,2,2,2,2,4),(0.,0.483827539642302,0.967624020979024,1.9341610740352,2.89116033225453,
3.84829645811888,4.80278850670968,5.75725253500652,6.7138923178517,7.67065760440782,
9.13465337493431,10.5993764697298,12.0672854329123,13.5349981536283,15.048524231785,
16.5622458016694,18.0740490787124,19.5854052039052,20.735429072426,21.8854027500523,
23.0338793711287,24.1820686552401,25.1139194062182,26.0455708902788,26.9758294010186,
27.9056233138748,28.5629173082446,29.2198319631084),.UNSPECIFIED.);
#504=CARTESIAN_POINT('',(6.79319247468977,37.2603716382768,42.2655982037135));
#505=VERTEX_POINT('',#504);
#506=EDGE_CURVE('E256',#444,#505,#503,.T.);
#507=ORIENTED_EDGE('',*,*,#506,.T.);
#508=CARTESIAN_POINT('',(2.71440865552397,39.9077935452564,35.44702474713));
#509=CARTESIAN_POINT('',(2.71854686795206,39.907512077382,35.4530354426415));
#510=CARTESIAN_POINT('',(2.72268476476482,39.9072254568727,35.4590461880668));
#511=CARTESIAN_POINT('',(2.96711840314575,39.8899885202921,35.814143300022));
#512=CARTESIAN_POINT('',(3.20631698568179,39.8556656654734,36.163385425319));
#513=CARTESIAN_POINT('',(3.67877457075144,39.7524306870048,36.8608453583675));
#514=CARTESIAN_POINT('',(3.91203147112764,39.6835064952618,37.2090627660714));
#515=CARTESIAN_POINT('',(4.36922583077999,39.5109721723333,37.9038529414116));
#516=CARTESIAN_POINT('',(4.59314877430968,39.4073101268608,38.2504224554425));
#517=CARTESIAN_POINT('',(5.02716309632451,39.1652943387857,38.9399718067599));
#518=CARTESIAN_POINT('',(5.23726075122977,39.0269564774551,39.282953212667));
#519=CARTESIAN_POINT('',(5.57172966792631,38.7677174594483,39.8497038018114));
#520=CARTESIAN_POINT('',(5.70123828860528,38.6565037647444,40.0749124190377));
#521=CARTESIAN_POINT('',(5.95056235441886,38.4187168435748,40.5224773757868));
#522=CARTESIAN_POINT('',(6.07038146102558,38.2921494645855,40.7448347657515));
#523=CARTESIAN_POINT('',(6.29865255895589,38.0236490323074,41.1860974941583));
#524=CARTESIAN_POINT('',(6.40710547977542,37.8817172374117,41.4050031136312));
#525=CARTESIAN_POINT('',(6.61072071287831,37.5824532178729,41.8387461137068));
#526=CARTESIAN_POINT('',(6.70587062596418,37.4251068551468,42.0535795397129));
#527=CARTESIAN_POINT('',(6.79329844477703,37.2601716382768,42.265855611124));
#528=B_SPLINE_CURVE_WITH_KNOTS('',3,(#508,#509,#510,#511,#512,#513,#514,#515,#516,#517,#518,
#519,#520,#521,#522,#523,#524,#525,#526,#527),.UNSPECIFIED.,.F.,.F.,(4,2,2,2,2,2,2,2,2,4),(0.,
0.0219089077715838,1.29430370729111,2.5671425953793,3.84189223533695,5.11605911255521,
5.96331589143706,6.81025099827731,7.65711679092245,8.5047667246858),.UNSPECIFIED.);
#529=EDGE_CURVE('E279',#157,#505,#528,.T.);
#530=ORIENTED_EDGE('',*,*,#529,.F.);
#531=ORIENTED_EDGE('',*,*,#158,.T.);
#532=CARTESIAN_POINT('',(-6.79329844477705,37.2601716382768,42.265855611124));
#533=CARTESIAN_POINT('',(-6.74168077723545,37.3575852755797,42.1404818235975));
#534=CARTESIAN_POINT('',(-6.68735057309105,37.4523535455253,42.0142139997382));
#535=CARTESIAN_POINT('',(-6.57371649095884,37.6365613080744,41.7600803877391));
#536=CARTESIAN_POINT('',(-6.51441360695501,37.7260018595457,41.632214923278));
#537=CARTESIAN_POINT('',(-6.32985122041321,37.9861045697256,41.2467679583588));
#538=CARTESIAN_POINT('',(-6.19780065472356,38.1488026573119,40.9870070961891));
#539=CARTESIAN_POINT('',(-5.91899816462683,38.4524867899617,40.4634896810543));
#540=CARTESIAN_POINT('',(-5.77226904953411,38.5935056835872,40.1997398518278));
#541=CARTESIAN_POINT('',(-5.46654460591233,38.8542124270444,39.6687220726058));
#542=CARTESIAN_POINT('',(-5.30754509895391,38.9738929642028,39.4014529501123));
#543=CARTESIAN_POINT('',(-4.9594507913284,39.2053524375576,38.8311770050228));
#544=CARTESIAN_POINT('',(-4.76906235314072,39.3143381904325,38.5278265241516));
#545=CARTESIAN_POINT('',(-4.37876726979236,39.50544670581,37.9187743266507));
#546=CARTESIAN_POINT('',(-4.17885937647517,39.5875659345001,37.613072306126));
#547=CARTESIAN_POINT('',(-3.77253619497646,39.7248494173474,37.0006483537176));
#548=CARTESIAN_POINT('',(-3.56613078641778,39.7800526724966,36.6939285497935));
#549=CARTESIAN_POINT('',(-3.14904403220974,39.863632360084,36.0797895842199));
#550=CARTESIAN_POINT('',(-2.93836388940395,39.8920162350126,35.7723706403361));
#551=CARTESIAN_POINT('',(-2.72268476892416,39.9072254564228,35.4590461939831));
#552=CARTESIAN_POINT('',(-2.71854687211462,39.9075120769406,35.4530354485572));
#553=CARTESIAN_POINT('',(-2.71440865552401,39.9077935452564,35.44702474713));
#554=B_SPLINE_CURVE_WITH_KNOTS('',3,(#532,#533,#534,#535,#536,#537,#538,#539,#540,#541,#542,
#543,#544,#545,#546,#547,#548,#549,#550,#551,#552,#553),.UNSPECIFIED.,.F.,.F.,(4,2,2,2,2,2,2,2,
2,2,4),(0.,0.500746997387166,1.00139413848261,2.00137868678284,2.99983278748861,
3.99862840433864,5.12056019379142,6.24263949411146,7.36308804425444,8.48322557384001,
8.50513448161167),.UNSPECIFIED.);
#555=CARTESIAN_POINT('',(-6.79319247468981,37.2603716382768,42.2655982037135));
#556=VERTEX_POINT('',#555);
#557=EDGE_CURVE('E285',#556,#153,#554,.T.);
#558=ORIENTED_EDGE('',*,*,#557,.F.);
#559=CARTESIAN_POINT('',(-6.79308650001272,37.2605716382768,42.2653407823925));
#560=CARTESIAN_POINT('',(-6.84295448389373,37.1664574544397,42.3864839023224));
#561=CARTESIAN_POINT('',(-6.89475631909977,37.0702087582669,42.5051386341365));
#562=CARTESIAN_POINT('',(-7.00228318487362,36.8738074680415,42.7373150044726));
#563=CARTESIAN_POINT('',(-7.05800796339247,36.7736551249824,42.8508369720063));
#564=CARTESIAN_POINT('',(-7.23103394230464,36.4680941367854,43.1832501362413));
#565=CARTESIAN_POINT('',(-7.35429536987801,36.2573745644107,43.3942536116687));
#566=CARTESIAN_POINT('',(-7.61539939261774,35.8273510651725,43.7921577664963));
#567=CARTESIAN_POINT('',(-7.75308609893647,35.6081523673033,43.9792757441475));
#568=CARTESIAN_POINT('',(-8.04382059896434,35.1624428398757,44.3316389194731));
#569=CARTESIAN_POINT('',(-8.19687058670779,34.9359309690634,44.4968809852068));
#570=CARTESIAN_POINT('',(-8.51735374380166,34.4794321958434,44.805373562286));
#571=CARTESIAN_POINT('',(-8.68474601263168,34.2494566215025,44.9486835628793));
#572=CARTESIAN_POINT('',(-9.03355708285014,33.7883224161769,45.2147473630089));
#573=CARTESIAN_POINT('',(-9.21497547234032,33.5571638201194,45.3375017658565));
#574=CARTESIAN_POINT('',(-9.59143177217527,33.0956864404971,45.5640349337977));
#575=CARTESIAN_POINT('',(-9.78649978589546,32.8653707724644,45.6677698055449));
#576=CARTESIAN_POINT('',(-10.1889814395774,32.4082820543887,45.8575407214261));
#577=CARTESIAN_POINT('',(-10.3963966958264,32.1815094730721,45.9435744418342));
#578=CARTESIAN_POINT('',(-10.9357222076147,31.6144699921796,46.1411102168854));
#579=CARTESIAN_POINT('',(-11.2753377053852,31.2777703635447,46.2419338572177));
#580=CARTESIAN_POINT('',(-11.978376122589,30.6217654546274,46.4126134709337));
#581=CARTESIAN_POINT('',(-12.3418107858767,30.30246889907,46.4824540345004));
#582=CARTESIAN_POINT('',(-13.0905088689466,29.6840405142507,46.5968280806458));
#583=CARTESIAN_POINT('',(-13.4758180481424,29.3849540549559,46.6413061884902));
#584=CARTESIAN_POINT('',(-14.2650968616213,28.8100959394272,46.7089216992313));
#585=CARTESIAN_POINT('',(-14.6690639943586,28.5343211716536,46.7320619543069));
#586=CARTESIAN_POINT('',(-15.5064196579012,27.9994985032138,46.7598841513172));
#587=CARTESIAN_POINT('',(-15.9403329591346,27.7412414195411,46.7639673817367));
#588=CARTESIAN_POINT('',(-16.8234491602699,27.2526731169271,46.7525338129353));
#589=CARTESIAN_POINT('',(-17.2726540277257,27.0223655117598,46.7370144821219));
#590=CARTESIAN_POINT('',(-18.1831087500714,26.5912128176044,46.684618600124));
#591=CARTESIAN_POINT('',(-18.6443426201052,26.3903307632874,46.6477691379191));
#592=CARTESIAN_POINT('',(-19.5761439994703,26.018766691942,46.5488547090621));
#593=CARTESIAN_POINT('',(-20.0467087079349,25.8480757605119,46.4867972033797));
#594=CARTESIAN_POINT('',(-20.879814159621,25.5748002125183,46.3503573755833));
#595=CARTESIAN_POINT('',(-21.2412851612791,25.4656891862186,46.2824684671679));
#596=CARTESIAN_POINT('',(-21.9647946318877,25.2656109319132,46.125849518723));
#597=CARTESIAN_POINT('',(-22.326833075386,25.1746429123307,46.0371203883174));
#598=CARTESIAN_POINT('',(-23.0479388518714,25.0109668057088,45.8358492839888));
#599=CARTESIAN_POINT('',(-23.4070094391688,24.9382351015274,45.723338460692));
#600=CARTESIAN_POINT('',(-24.1188549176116,24.8105624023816,45.4714698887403));
#601=CARTESIAN_POINT('',(-24.471631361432,24.7556169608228,45.3321188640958));
#602=CARTESIAN_POINT('',(-25.1009857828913,24.6714549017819,45.0531347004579));
#603=CARTESIAN_POINT('',(-25.3793967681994,24.6393411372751,44.9185019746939));
#604=CARTESIAN_POINT('',(-25.9265253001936,24.5855801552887,44.629009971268));
#605=CARTESIAN_POINT('',(-26.1952449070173,24.5639307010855,44.4741550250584));
#606=CARTESIAN_POINT('',(-26.7198900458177,24.530146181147,44.1439784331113));
#607=CARTESIAN_POINT('',(-26.9758341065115,24.5179969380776,43.9686877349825));
#608=CARTESIAN_POINT('',(-27.4725234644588,24.5019339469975,43.5975808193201));
#609=CARTESIAN_POINT('',(-27.7132762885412,24.498016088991,43.401774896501));
#610=CARTESIAN_POINT('',(-28.1090728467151,24.4971100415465,43.0505610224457));
#611=CARTESIAN_POINT('',(-28.2685572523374,24.4984274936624,42.9001311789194));
#612=CARTESIAN_POINT('',(-28.5777746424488,24.5038795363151,42.5897862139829));
#613=CARTESIAN_POINT('',(-28.7275132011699,24.5080125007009,42.4298766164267));
#614=CARTESIAN_POINT('',(-28.8720321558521,24.5132703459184,42.265370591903));
#615=B_SPLINE_CURVE_WITH_KNOTS('',3,(#559,#560,#561,#562,#563,#564,#565,#566,#567,#568,#569,
#570,#571,#572,#573,#574,#575,#576,#577,#578,#579,#580,#581,#582,#583,#584,#585,#586,#587,#588,
#589,#590,#591,#592,#593,#594,#595,#596,#597,#598,#599,#600,#601,#602,#603,#604,#605,#606,#607,
#608,#609,#610,#611,#612,#613,#614),.UNSPECIFIED.,.F.,.F.,(4,2,2,2,2,2,2,2,2,2,2,2,2,2,2,2,2,2,
2,2,2,2,2,2,2,2,2,4),(0.,0.483826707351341,0.96762235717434,1.93415776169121,2.89115545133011,
3.84829000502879,4.80278053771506,5.7572430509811,6.71388128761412,7.67064502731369,
9.13463558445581,10.599353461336,12.0672571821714,13.5349646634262,15.0484857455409,
16.5622023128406,18.0740006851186,19.5853519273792,20.7353824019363,21.8853626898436,
23.0338458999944,24.1820417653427,25.1138944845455,26.0455479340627,26.9758083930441,
27.9056042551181,28.5629077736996,29.2198319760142),.UNSPECIFIED.);
#616=CARTESIAN_POINT('',(-28.8718321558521,24.5132630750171,42.2655982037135));
#617=VERTEX_POINT('',#616);
#618=EDGE_CURVE('E291',#556,#617,#615,.T.);
#619=ORIENTED_EDGE('',*,*,#618,.T.);
#620=CARTESIAN_POINT('',(-33.2039586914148,22.3046436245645,35.44702474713));
#621=CARTESIAN_POINT('',(-33.2016458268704,22.3080866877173,35.4530354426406));
#622=CARTESIAN_POINT('',(-33.1993286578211,22.3115269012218,35.4590461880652));
#623=CARTESIAN_POINT('',(-33.0621842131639,22.5145941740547,35.8141433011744));
#624=CARTESIAN_POINT('',(-32.9128604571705,22.7045847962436,36.1633854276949));
#625=CARTESIAN_POINT('',(-32.5872275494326,23.0621275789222,36.860845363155));
#626=CARTESIAN_POINT('',(-32.4109089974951,23.2296718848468,37.2090627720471));
#627=CARTESIAN_POINT('',(-32.0328927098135,23.5393466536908,37.9038529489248));
#628=CARTESIAN_POINT('',(-31.8311572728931,23.681438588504,38.2504224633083));
#629=CARTESIAN_POINT('',(-31.4045582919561,23.9362981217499,38.9399718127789));
#630=CARTESIAN_POINT('',(-31.1797053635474,24.0490790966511,39.2829532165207));
#631=CARTESIAN_POINT('',(-30.787965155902,24.2091174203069,39.8497011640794));
#632=CARTESIAN_POINT('',(-30.626898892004,24.2656677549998,40.0749071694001));
#633=CARTESIAN_POINT('',(-30.2963113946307,24.362694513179,40.5224669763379));
#634=CARTESIAN_POINT('',(-30.1267933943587,24.4031770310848,40.7448218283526));
#635=CARTESIAN_POINT('',(-29.7801340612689,24.4666154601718,41.1860795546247));
#636=CARTESIAN_POINT('',(-29.6029933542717,24.4895728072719,41.4049827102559));
#637=CARTESIAN_POINT('',(-29.2420201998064,24.5162777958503,41.8387209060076));
#638=CARTESIAN_POINT('',(-29.058181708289,24.5200076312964,42.0535519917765));
#639=CARTESIAN_POINT('',(-28.8716321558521,24.5132558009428,42.2658258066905));
#640=B_SPLINE_CURVE_WITH_KNOTS('',3,(#620,#621,#622,#623,#624,#625,#626,#627,#628,#629,#630,
#631,#632,#633,#634,#635,#636,#637,#638,#639),.UNSPECIFIED.,.F.,.F.,(4,2,2,2,2,2,2,2,2,4),(0.,
0.0219089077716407,1.29430371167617,2.56714260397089,3.8418922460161,5.1160591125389,
5.96330602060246,6.8102312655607,7.65708711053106,8.50472706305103),.UNSPECIFIED.);
#641=EDGE_CURVE('E298',#130,#617,#640,.T.);
#642=ORIENTED_EDGE('',*,*,#641,.F.);
#643=ORIENTED_EDGE('',*,*,#131,.T.);
#644=CARTESIAN_POINT('',(-35.6648992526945,12.7469085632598,42.2658666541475));
#645=CARTESIAN_POINT('',(-35.7234532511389,12.8403174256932,42.1404930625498));
#646=CARTESIAN_POINT('',(-35.7783600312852,12.934752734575,42.0142254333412));
#647=CARTESIAN_POINT('',(-35.8810719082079,13.1252663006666,41.7600922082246));
#648=CARTESIAN_POINT('',(-35.9288784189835,13.2213442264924,41.6322269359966));
#649=CARTESIAN_POINT('',(-36.0618532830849,13.5112308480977,41.2467805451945));
#650=CARTESIAN_POINT('',(-36.1367290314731,13.7069387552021,40.9870200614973));
#651=CARTESIAN_POINT('',(-36.2603267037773,14.1002303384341,40.463503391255));
#652=CARTESIAN_POINT('',(-36.3090884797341,14.2978106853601,40.1997539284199));
#653=CARTESIAN_POINT('',(-36.3820057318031,14.6929287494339,39.668736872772));
#654=CARTESIAN_POINT('',(-36.4061527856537,14.8904664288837,39.4014681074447));
#655=CARTESIAN_POINT('',(-36.4325564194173,15.3076554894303,38.8311912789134));
#656=CARTESIAN_POINT('',(-36.4317470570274,15.5270305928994,38.5278395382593));
#657=CARTESIAN_POINT('',(-36.4021049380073,15.9605923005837,37.9187847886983));
#658=CARTESIAN_POINT('',(-36.3732684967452,16.1747782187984,37.61308147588));
#659=CARTESIAN_POINT('',(-36.2889979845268,16.5953080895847,37.0006549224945));
#660=CARTESIAN_POINT('',(-36.2336026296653,16.8016629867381,36.6939338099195));
#661=CARTESIAN_POINT('',(-36.0974410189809,17.2046623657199,36.0797922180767));
#662=CARTESIAN_POINT('',(-36.0166818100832,17.401309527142,35.7723719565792));
#663=CARTESIAN_POINT('',(-35.9220134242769,17.595698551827,35.4590461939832));
#664=CARTESIAN_POINT('',(-35.920192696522,17.5994253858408,35.4530354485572));
#665=CARTESIAN_POINT('',(-35.9183673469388,17.603149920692,35.44702474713));
#666=B_SPLINE_CURVE_WITH_KNOTS('',3,(#644,#645,#646,#647,#648,#649,#650,#651,#652,#653,#654,
#655,#656,#657,#658,#659,#660,#661,#662,#663,#664,#665),.UNSPECIFIED.,.F.,.F.,(4,2,2,2,2,2,2,2,
2,2,4),(0.,0.500746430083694,1.00139300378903,2.00137641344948,2.9998293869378,3.99862388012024,
5.12056047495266,6.24264458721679,7.36309793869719,8.48324026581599,8.50514917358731),.UNSPECIFIED.);
#667=CARTESIAN_POINT('',(-35.6650246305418,12.7471085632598,42.2655982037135));
#668=VERTEX_POINT('',#667);
#669=EDGE_CURVE('E321',#668,#126,#666,.T.);
#670=ORIENTED_EDGE('',*,*,#669,.F.);
#671=CARTESIAN_POINT('',(-35.6651500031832,12.7473085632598,42.2653297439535));
#672=CARTESIAN_POINT('',(-35.6085788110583,12.657064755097,42.3864729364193));
#673=CARTESIAN_POINT('',(-35.5511259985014,12.5640789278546,42.505127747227));
#674=CARTESIAN_POINT('',(-35.4348010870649,12.372757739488,42.7373042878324));
#675=CARTESIAN_POINT('',(-35.3759290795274,12.2744227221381,42.8508263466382));
#676=CARTESIAN_POINT('',(-35.1978187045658,11.9717980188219,43.1832398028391));
#677=CARTESIAN_POINT('',(-35.0769610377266,11.759691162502,43.3942434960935));
#678=CARTESIAN_POINT('',(-34.8351019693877,11.3185575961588,43.7921481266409));
#679=CARTESIAN_POINT('',(-34.7141137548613,11.0897185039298,43.9792663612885));
#680=CARTESIAN_POINT('',(-34.4734853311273,10.6150811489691,44.3316300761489));
#681=CARTESIAN_POINT('',(-34.3538453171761,10.3692804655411,44.4968724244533));
#682=CARTESIAN_POINT('',(-34.118747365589,9.86348535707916,44.8053655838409));
#683=CARTESIAN_POINT('',(-34.003278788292,9.60353201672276,44.9486758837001));
#684=CARTESIAN_POINT('',(-33.7783302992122,9.07088645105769,45.2147402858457));
#685=CARTESIAN_POINT('',(-33.6688502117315,8.79819459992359,45.3374949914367));
#686=CARTESIAN_POINT('',(-33.4574270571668,8.24143593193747,45.5640287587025));
#687=CARTESIAN_POINT('',(-33.355501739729,7.95734460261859,45.6677639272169));
#688=CARTESIAN_POINT('',(-33.1608918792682,7.38024160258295,45.8575354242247));
#689=CARTESIAN_POINT('',(-33.0682085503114,7.08722876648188,45.9435694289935));
#690=CARTESIAN_POINT('',(-32.8468004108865,6.33664057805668,46.1411058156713));
#691=CARTESIAN_POINT('',(-32.7250175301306,5.87417592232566,46.2419297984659));
#692=CARTESIAN_POINT('',(-32.5084193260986,4.93732591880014,46.412610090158));
#693=CARTESIAN_POINT('',(-32.4136174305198,4.4629347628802,46.4824509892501));
#694=CARTESIAN_POINT('',(-32.252391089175,3.50533052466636,46.5968256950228));
#695=CARTESIAN_POINT('',(-32.1860288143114,3.02210049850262,46.6413041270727));
#696=CARTESIAN_POINT('',(-32.0828256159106,2.05113738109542,46.7089202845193));
#697=CARTESIAN_POINT('',(-32.0459807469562,1.56340490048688,46.7320608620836));
#698=CARTESIAN_POINT('',(-32.0014874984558,0.570823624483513,46.7598837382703));
#699=CARTESIAN_POINT('',(-31.9947863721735,0.0659157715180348,46.7639673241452));
#700=CARTESIAN_POINT('',(-32.0132306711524,-0.943168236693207,46.7525345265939));
#701=CARTESIAN_POINT('',(-32.0383802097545,-1.4473442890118,46.7370156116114));
#702=CARTESIAN_POINT('',(-32.1202170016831,-2.45139648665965,46.6846206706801));
#703=CARTESIAN_POINT('',(-32.1768642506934,-2.95127727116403,46.647771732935));
#704=CARTESIAN_POINT('',(-32.3209795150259,-3.94402208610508,46.5488585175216));
#705=CARTESIAN_POINT('',(-32.4084384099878,-4.43688814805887,46.4868017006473));
#706=CARTESIAN_POINT('',(-32.5883264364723,-5.29501706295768,46.3503630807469));
#707=CARTESIAN_POINT('',(-32.6745687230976,-5.66261664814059,46.2824745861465));
#708=CARTESIAN_POINT('',(-32.8630501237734,-6.3892353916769,46.1258564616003));
#709=CARTESIAN_POINT('',(-32.9652885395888,-6.74825492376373,46.037127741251));
#710=CARTESIAN_POINT('',(-33.1840934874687,-7.45459097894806,45.8358574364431));
#711=CARTESIAN_POINT('',(-33.3006411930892,-7.80192212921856,45.723347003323));
#712=CARTESIAN_POINT('',(-33.5459960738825,-8.48223685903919,45.4714791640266));
#713=CARTESIAN_POINT('',(-33.6748001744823,-8.81522400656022,45.3321284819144));
#714=CARTESIAN_POINT('',(-33.9165908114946,-9.40234329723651,45.0531451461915));
#715=CARTESIAN_POINT('',(-34.0279848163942,-9.65951147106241,44.9185129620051));
#716=CARTESIAN_POINT('',(-34.2549904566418,-10.1602198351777,44.6290220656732));
#717=CARTESIAN_POINT('',(-34.3706011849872,-10.4037629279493,44.4741676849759));
#718=CARTESIAN_POINT('',(-34.6036653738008,-10.8750119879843,44.1439922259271));
#719=CARTESIAN_POINT('',(-34.7211158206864,-11.1027410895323,43.9687020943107));
#720=CARTESIAN_POINT('',(-34.9555495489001,-11.5409190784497,43.5975963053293));
#721=CARTESIAN_POINT('',(-35.0725330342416,-11.7513765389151,43.4017909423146));
#722=CARTESIAN_POINT('',(-35.2696517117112,-12.0946088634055,43.0505692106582));
#723=CARTESIAN_POINT('',(-35.3505397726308,-12.2320760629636,42.9001303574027));
#724=CARTESIAN_POINT('',(-35.5098795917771,-12.4971557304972,42.5897662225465));
#725=CARTESIAN_POINT('',(-35.5883327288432,-12.6247738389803,42.4298464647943));
#726=CARTESIAN_POINT('',(-35.6651500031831,-12.74730856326,42.2653297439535));
#727=B_SPLINE_CURVE_WITH_KNOTS('',3,(#671,#672,#673,#674,#675,#676,#677,#678,#679,#680,#681,
#682,#683,#684,#685,#686,#687,#688,#689,#690,#691,#692,#693,#694,#695,#696,#697,#698,#699,#700,
#701,#702,#703,#704,#705,#706,#707,#708,#709,#710,#711,#712,#713,#714,#715,#716,#717,#718,#719,
#720,#721,#722,#723,#724,#725,#726),.UNSPECIFIED.,.F.,.F.,(4,2,2,2,2,2,2,2,2,2,2,2,2,2,2,2,2,2,
2,2,2,2,2,2,2,2,2,4),(0.,0.483826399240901,0.967621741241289,1.93415653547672,2.89115364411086,
3.84828761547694,4.80277758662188,5.75723953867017,6.7138772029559,7.67064037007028,
9.1346289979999,10.5993449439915,12.0672467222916,13.5349522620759,15.0484714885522,
16.5621861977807,18.0739827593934,19.5853321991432,20.7353651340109,21.8853478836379,
23.0338335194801,24.1820318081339,25.1138844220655,26.0455377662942,26.9757981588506,
27.9055939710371,28.5629371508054,29.2199010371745),.UNSPECIFIED.);
#728=CARTESIAN_POINT('',(-35.6650246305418,-12.74710856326,42.2655982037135));
#729=VERTEX_POINT('',#728);
#730=EDGE_CURVE('E327',#668,#729,#727,.T.);
#731=ORIENTED_EDGE('',*,*,#730,.T.);
#732=CARTESIAN_POINT('',(-35.9183673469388,-17.603149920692,35.44702474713));
#733=CARTESIAN_POINT('',(-35.9201926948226,-17.5994253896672,35.4530354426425));
#734=CARTESIAN_POINT('',(-35.922013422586,-17.5956985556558,35.4590461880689));
#735=CARTESIAN_POINT('',(-36.029302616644,-17.3753943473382,35.8141432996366));
#736=CARTESIAN_POINT('',(-36.1191774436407,-17.1510808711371,36.1633854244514));
#737=CARTESIAN_POINT('',(-36.2660021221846,-16.6903031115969,36.8608453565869));
#738=CARTESIAN_POINT('',(-36.3229404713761,-16.4538346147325,37.2090627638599));
#739=CARTESIAN_POINT('',(-36.4021185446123,-15.9716255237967,37.903852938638));
#740=CARTESIAN_POINT('',(-36.424306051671,-15.7258715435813,38.2504224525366));
#741=CARTESIAN_POINT('',(-36.4317213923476,-15.2289962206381,38.9399718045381));
#742=CARTESIAN_POINT('',(-36.4169661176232,-14.9778773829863,39.2829532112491));
#743=CARTESIAN_POINT('',(-36.359692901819,-14.5585985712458,39.8497047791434));
#744=CARTESIAN_POINT('',(-36.3281331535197,-14.3908332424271,40.0749143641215));
#745=CARTESIAN_POINT('',(-36.2468651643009,-14.0560173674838,40.522481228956));
#746=CARTESIAN_POINT('',(-36.1971638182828,-13.8889665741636,40.7448395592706));
#747=CARTESIAN_POINT('',(-36.0787703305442,-13.5570263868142,41.1861041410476));
#748=CARTESIAN_POINT('',(-36.0100797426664,-13.3921368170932,41.4050106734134));
#749=CARTESIAN_POINT('',(-35.8527159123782,-13.0661675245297,41.8387554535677));
#750=CARTESIAN_POINT('',(-35.7640242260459,-12.9050914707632,42.0535897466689));
#751=CARTESIAN_POINT('',(-35.6648992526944,-12.7469085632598,42.2658666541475));
#752=B_SPLINE_CURVE_WITH_KNOTS('',3,(#732,#733,#734,#735,#736,#737,#738,#739,#740,#741,#742,
#743,#744,#745,#746,#747,#748,#749,#750,#751),.UNSPECIFIED.,.F.,.F.,(4,2,2,2,2,2,2,2,2,4),(0.,
0.0219089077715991,1.29430370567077,2.56714259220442,3.84189223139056,5.11605911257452,
5.96331954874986,6.81025830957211,7.65712778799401,8.5047814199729),.UNSPECIFIED.);
#753=EDGE_CURVE('E334',#103,#729,#752,.T.);
#754=ORIENTED_EDGE('',*,*,#753,.F.);
#755=ORIENTED_EDGE('',*,*,#104,.T.);
#756=CARTESIAN_POINT('',(-28.871632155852,-24.5132558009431,42.2658258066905));
#757=CARTESIAN_POINT('',(-28.9818038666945,-24.5172598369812,42.1404514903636));
#758=CARTESIAN_POINT('',(-29.091040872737,-24.5175920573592,42.0141831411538));
#759=CARTESIAN_POINT('',(-29.3073868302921,-24.5112847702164,41.7600484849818));
#760=CARTESIAN_POINT('',(-29.4144962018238,-24.5046466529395,41.6321825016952));
#761=CARTESIAN_POINT('',(-29.7320333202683,-24.4748605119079,41.2467339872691));
#762=CARTESIAN_POINT('',(-29.9389594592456,-24.4418492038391,40.9869721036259));
#763=CARTESIAN_POINT('',(-30.341359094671,-24.3522387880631,40.4634526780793));
#764=CARTESIAN_POINT('',(-30.5368496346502,-24.2956758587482,40.1997018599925));
#765=CARTESIAN_POINT('',(-30.9154904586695,-24.1612616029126,39.6686821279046));
#766=CARTESIAN_POINT('',(-31.0986364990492,-24.0834030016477,39.4014120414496));
#767=CARTESIAN_POINT('',(-31.4731301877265,-23.8976729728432,38.8311384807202));
#768=CARTESIAN_POINT('',(-31.6627059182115,-23.7872849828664,38.5277913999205));
#769=CARTESIAN_POINT('',(-32.0233528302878,-23.5448350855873,37.9187460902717));
#770=CARTESIAN_POINT('',(-32.1944215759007,-23.4127703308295,37.6130475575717));
#771=CARTESIAN_POINT('',(-32.5164695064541,-23.1295282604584,37.0006306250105));
#772=CARTESIAN_POINT('',(-32.6674775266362,-22.9783790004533,36.6939143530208));
#773=CARTESIAN_POINT('',(-32.9483992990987,-22.658964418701,36.0797824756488));
#774=CARTESIAN_POINT('',(-33.0783188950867,-22.4907038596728,35.77236708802));
#775=CARTESIAN_POINT('',(-33.1993286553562,-22.3115269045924,35.4590461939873));
#776=CARTESIAN_POINT('',(-33.2016458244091,-22.3080866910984,35.4530354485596));
#777=CARTESIAN_POINT('',(-33.2039586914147,-22.3046436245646,35.44702474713));
#778=B_SPLINE_CURVE_WITH_KNOTS('',3,(#756,#757,#758,#759,#760,#761,#762,#763,#764,#765,#766,
#767,#768,#769,#770,#771,#772,#773,#774,#775,#776,#777),.UNSPECIFIED.,.F.,.F.,(4,2,2,2,2,2,2,2,
2,2,4),(0.,0.50074852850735,1.00139720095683,2.00138482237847,2.99984196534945,3.99864061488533,
5.12055943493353,6.24262574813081,7.36306133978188,8.48318592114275,8.50509482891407),.UNSPECIFIED.);
#779=CARTESIAN_POINT('',(-28.8718321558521,-24.5132630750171,42.2655982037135));
#780=VERTEX_POINT('',#779);
#781=EDGE_CURVE('E340',#780,#99,#778,.T.);
#782=ORIENTED_EDGE('',*,*,#781,.F.);
#783=CARTESIAN_POINT('',(-28.8720321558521,-24.5132703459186,42.265370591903));
#784=CARTESIAN_POINT('',(-28.7655922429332,-24.5094002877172,42.3865135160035));
#785=CARTESIAN_POINT('',(-28.6563368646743,-24.5061377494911,42.505168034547));
#786=CARTESIAN_POINT('',(-28.432483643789,-24.5010583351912,42.7373439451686));
#787=CARTESIAN_POINT('',(-28.3178861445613,-24.4992413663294,42.8508656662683));
#788=CARTESIAN_POINT('',(-27.9667476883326,-24.4963061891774,43.1832780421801));
#789=CARTESIAN_POINT('',(-27.7226272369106,-24.4976942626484,43.3942809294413));
#790=CARTESIAN_POINT('',(-27.2196615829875,-24.5088059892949,43.7921837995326));
#791=CARTESIAN_POINT('',(-26.9609854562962,-24.5184472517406,43.9793010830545));
#792=CARTESIAN_POINT('',(-26.4296202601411,-24.547376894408,44.3316628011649));
#793=CARTESIAN_POINT('',(-26.1569291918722,-24.5666666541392,44.4969041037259));
#794=CARTESIAN_POINT('',(-25.6013461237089,-24.6159649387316,44.8053951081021));
#795=CARTESIAN_POINT('',(-25.3184843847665,-24.6459437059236,44.9487043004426));
#796=CARTESIAN_POINT('',(-24.744723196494,-24.717457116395,45.2147664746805));
#797=CARTESIAN_POINT('',(-24.4538239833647,-24.7589914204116,45.3375200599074));
#798=CARTESIAN_POINT('',(-23.8659431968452,-24.8542748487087,45.5640516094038));
#799=CARTESIAN_POINT('',(-23.5689492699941,-24.9080516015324,45.6677856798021));
#800=CARTESIAN_POINT('',(-22.9718567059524,-25.0280680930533,45.8575550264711));
#801=CARTESIAN_POINT('',(-22.6717576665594,-25.0943094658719,45.9435879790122));
#802=CARTESIAN_POINT('',(-21.9110220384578,-25.2778615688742,46.1411221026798));
#803=CARTESIAN_POINT('',(-21.4496222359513,-25.4036289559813,46.2419448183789));
#804=CARTESIAN_POINT('',(-20.5299830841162,-25.6844789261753,46.4126226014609));
#805=CARTESIAN_POINT('',(-20.0717454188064,-25.8395760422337,46.482462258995));
#806=CARTESIAN_POINT('',(-19.1618190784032,-26.1787570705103,46.5968345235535));
#807=CARTESIAN_POINT('',(-18.7101468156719,-26.3629032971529,46.6413117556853));
#808=CARTESIAN_POINT('',(-17.8176634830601,-26.7590137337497,46.7089255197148));
#809=CARTESIAN_POINT('',(-17.3768509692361,-26.9709742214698,46.7320649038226));
#810=CARTESIAN_POINT('',(-16.4950014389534,-27.4287384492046,46.7598852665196));
#811=CARTESIAN_POINT('',(-16.0543869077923,-27.6753920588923,46.7639675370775));
#812=CARTESIAN_POINT('',(-15.1897151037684,-28.1959134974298,46.7525318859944));
#813=CARTESIAN_POINT('',(-14.7656599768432,-28.4697848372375,46.7370114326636));
#814=CARTESIAN_POINT('',(-13.9370427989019,-29.0426900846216,46.684613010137));
#815=CARTESIAN_POINT('',(-13.5324567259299,-29.3416916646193,46.6477621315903));
#816=CARTESIAN_POINT('',(-12.7447720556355,-29.9628780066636,46.5488444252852));
#817=CARTESIAN_POINT('',(-12.3616671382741,-30.2850558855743,46.4867850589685));
#818=CARTESIAN_POINT('',(-11.708453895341,-30.8699103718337,46.3503419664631));
#819=CARTESIAN_POINT('',(-11.4332282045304,-31.1283972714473,46.2824519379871));
#820=CARTESIAN_POINT('',(-10.8982060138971,-31.6549341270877,46.1258307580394));
#821=CARTESIAN_POINT('',(-10.6384088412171,-31.9229836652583,46.0371005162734));
#822=CARTESIAN_POINT('',(-10.1361135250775,-32.4656393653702,45.8358272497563));
#823=CARTESIAN_POINT('',(-9.89359330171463,-32.7402365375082,45.7233153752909));
#824=CARTESIAN_POINT('',(-9.42710779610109,-33.292873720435,45.4714448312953));
#825=CARTESIAN_POINT('',(-9.20313788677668,-33.5709128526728,45.3320928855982));
#826=CARTESIAN_POINT('',(-8.81557789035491,-34.073866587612,45.0531067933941));
#827=CARTESIAN_POINT('',(-8.64856236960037,-34.2989200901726,44.9184729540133));
#828=CARTESIAN_POINT('',(-8.32844232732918,-34.7458654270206,44.6289787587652));
#829=CARTESIAN_POINT('',(-8.17533483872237,-34.9677579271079,44.4741227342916));
#830=CARTESIAN_POINT('',(-7.8837565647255,-35.4052199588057,44.1439440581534));
#831=CARTESIAN_POINT('',(-7.7452642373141,-35.6207984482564,43.9686523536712));
#832=CARTESIAN_POINT('',(-7.48301106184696,-36.0429105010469,43.5975435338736));
#833=CARTESIAN_POINT('',(-7.3592428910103,-36.2494485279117,43.4017367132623));
#834=CARTESIAN_POINT('',(-7.16056297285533,-36.5917616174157,43.0505232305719));
#835=CARTESIAN_POINT('',(-7.08196345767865,-36.7305353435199,42.900094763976));
#836=CARTESIAN_POINT('',(-6.93207963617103,-37.001046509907,42.5897528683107));
#837=CARTESIAN_POINT('',(-6.86079113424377,-37.132787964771,42.429844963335));
#838=CARTESIAN_POINT('',(-6.79308650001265,-37.2605716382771,42.2653407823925));
#839=B_SPLINE_CURVE_WITH_KNOTS('',3,(#783,#784,#785,#786,#787,#788,#789,#790,#791,#792,#793,
#794,#795,#796,#797,#798,#799,#800,#801,#802,#803,#804,#805,#806,#807,#808,#809,#810,#811,#812,
#813,#814,#815,#816,#817,#818,#819,#820,#821,#822,#823,#824,#825,#826,#827,#828,#829,#830,#831,
#832,#833,#834,#835,#836,#837,#838),.UNSPECIFIED.,.F.,.F.,(4,2,2,2,2,2,2,2,2,2,2,2,2,2,2,2,2,2,
2,2,2,2,2,2,2,2,2,4),(0.,0.483827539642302,0.967624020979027,1.93416107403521,2.89116033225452,
3.84829645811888,4.8027885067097,5.75725253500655,6.71389231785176,7.6706576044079,
9.13465337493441,10.5993764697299,12.0672854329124,13.5349981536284,15.0485242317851,
16.5622458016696,18.0740490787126,19.5854052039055,20.7354290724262,21.8854027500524,
23.0338793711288,24.1820686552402,25.1139194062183,26.0455708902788,26.9758294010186,
27.9056233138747,28.5629173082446,29.2198319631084),.UNSPECIFIED.);
#840=CARTESIAN_POINT('',(-6.79319247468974,-37.2603716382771,42.2655982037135));
#841=VERTEX_POINT('',#840);
#842=EDGE_CURVE('E364',#780,#841,#839,.T.);
#843=ORIENTED_EDGE('',*,*,#842,.T.);
#844=CARTESIAN_POINT('',(-2.71440865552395,-39.9077935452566,35.44702474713));
#845=CARTESIAN_POINT('',(-2.71854686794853,-39.9075120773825,35.4530354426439));
#846=CARTESIAN_POINT('',(-2.72268476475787,-39.9072254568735,35.4590461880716));
#847=CARTESIAN_POINT('',(-2.96711840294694,-39.889988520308,35.8141433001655));
#848=CARTESIAN_POINT('',(-3.2063169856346,-39.8556656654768,36.1633854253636));
#849=CARTESIAN_POINT('',(-3.67877457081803,-39.7524306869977,36.8608453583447));
#850=CARTESIAN_POINT('',(-3.91203147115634,-39.6835064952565,37.2090627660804));
#851=CARTESIAN_POINT('',(-4.36922583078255,-39.5109721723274,37.9038529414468));
#852=CARTESIAN_POINT('',(-4.59314877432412,-39.4073101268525,38.2504224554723));
#853=CARTESIAN_POINT('',(-5.0271630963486,-39.1652943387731,38.9399718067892));
#854=CARTESIAN_POINT('',(-5.23726075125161,-39.0269564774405,39.2829532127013));
#855=CARTESIAN_POINT('',(-5.571729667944,-38.767717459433,39.8497038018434));
#856=CARTESIAN_POINT('',(-5.70123828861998,-38.6565037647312,40.0749124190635));
#857=CARTESIAN_POINT('',(-5.95056235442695,-38.4187168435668,40.5224773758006));
#858=CARTESIAN_POINT('',(-6.07038146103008,-38.2921494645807,40.7448347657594));
#859=CARTESIAN_POINT('',(-6.29865255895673,-38.0236490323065,41.1860974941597));
#860=CARTESIAN_POINT('',(-6.40710547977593,-37.8817172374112,41.4050031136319));
#861=CARTESIAN_POINT('',(-6.61072071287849,-37.582453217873,41.8387461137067));
#862=CARTESIAN_POINT('',(-6.70587062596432,-37.4251068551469,42.0535795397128));
#863=CARTESIAN_POINT('',(-6.793298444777,-37.2601716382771,42.265855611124));
#864=B_SPLINE_CURVE_WITH_KNOTS('',3,(#844,#845,#846,#847,#848,#849,#850,#851,#852,#853,#854,
#855,#856,#857,#858,#859,#860,#861,#862,#863),.UNSPECIFIED.,.F.,.F.,(4,2,2,2,2,2,2,2,2,4),(0.,
0.0219089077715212,1.29430370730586,2.56714259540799,3.8418922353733,5.11605911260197,
5.96331589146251,6.81025099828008,7.65711679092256,8.5047667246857),.UNSPECIFIED.);
#865=EDGE_CURVE('E371',#76,#841,#864,.T.);
#866=ORIENTED_EDGE('',*,*,#865,.F.);
#867=ORIENTED_EDGE('',*,*,#77,.T.);
#868=CARTESIAN_POINT('',(6.79329844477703,-37.2601716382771,42.265855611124));
#869=CARTESIAN_POINT('',(6.74168077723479,-37.3575852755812,42.1404818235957));
#870=CARTESIAN_POINT('',(6.68735057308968,-37.4523535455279,42.0142139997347));
#871=CARTESIAN_POINT('',(6.57371649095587,-37.6365613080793,41.7600803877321));
#872=CARTESIAN_POINT('',(6.51441360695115,-37.7260018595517,41.6322149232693));
#873=CARTESIAN_POINT('',(6.32985122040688,-37.9861045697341,41.2467679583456));
#874=CARTESIAN_POINT('',(6.1978006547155,-38.1488026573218,40.9870070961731));
#875=CARTESIAN_POINT('',(5.91899816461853,-38.4524867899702,40.4634896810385));
#876=CARTESIAN_POINT('',(5.77226904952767,-38.5935056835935,40.1997398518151));
#877=CARTESIAN_POINT('',(5.46654460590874,-38.8542124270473,39.6687220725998));
#878=CARTESIAN_POINT('',(5.30754509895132,-38.9738929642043,39.4014529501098));
#879=CARTESIAN_POINT('',(4.95945079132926,-39.2053524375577,38.8311770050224));
#880=CARTESIAN_POINT('',(4.76906235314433,-39.3143381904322,38.5278265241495));
#881=CARTESIAN_POINT('',(4.37876726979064,-39.5054467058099,37.9187743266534));
#882=CARTESIAN_POINT('',(4.17885937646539,-39.5875659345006,37.6130723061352));
#883=CARTESIAN_POINT('',(3.77253619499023,-39.7248494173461,37.0006483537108));
#884=CARTESIAN_POINT('',(3.56613078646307,-39.7800526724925,36.6939285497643));
#885=CARTESIAN_POINT('',(3.14904403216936,-39.8636323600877,36.0797895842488));
#886=CARTESIAN_POINT('',(2.93836388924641,-39.8920162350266,35.7723706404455));
#887=CARTESIAN_POINT('',(2.72268476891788,-39.9072254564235,35.4590461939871));
#888=CARTESIAN_POINT('',(2.71854687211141,-39.9075120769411,35.4530354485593));
#889=CARTESIAN_POINT('',(2.71440865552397,-39.9077935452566,35.44702474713));
#890=B_SPLINE_CURVE_WITH_KNOTS('',3,(#868,#869,#870,#871,#872,#873,#874,#875,#876,#877,#878,
#879,#880,#881,#882,#883,#884,#885,#886,#887,#888,#889),.UNSPECIFIED.,.F.,.F.,(4,2,2,2,2,2,2,2,
2,2,4),(0.,0.500746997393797,1.00139413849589,2.0013786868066,2.99983278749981,3.99862840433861,
5.12056019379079,6.24263949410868,7.363088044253,8.48322557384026,8.50513448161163),.UNSPECIFIED.);
#891=CARTESIAN_POINT('',(6.79319247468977,-37.2603716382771,42.2655982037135));
#892=VERTEX_POINT('',#891);
#893=EDGE_CURVE('E377',#892,#72,#890,.T.);
#894=ORIENTED_EDGE('',*,*,#893,.F.);
#895=CARTESIAN_POINT('',(6.79308650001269,-37.2605716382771,42.2653407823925));
#896=CARTESIAN_POINT('',(6.84295448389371,-37.1664574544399,42.3864839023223));
#897=CARTESIAN_POINT('',(6.89475631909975,-37.070208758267,42.5051386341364));
#898=CARTESIAN_POINT('',(7.00228318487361,-36.8738074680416,42.7373150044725));
#899=CARTESIAN_POINT('',(7.05800796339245,-36.7736551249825,42.8508369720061));
#900=CARTESIAN_POINT('',(7.23103394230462,-36.4680941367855,43.1832501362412));
#901=CARTESIAN_POINT('',(7.35429536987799,-36.2573745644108,43.3942536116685));
#902=CARTESIAN_POINT('',(7.61539939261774,-35.8273510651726,43.7921577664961));
#903=CARTESIAN_POINT('',(7.75308609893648,-35.6081523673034,43.9792757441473));
#904=CARTESIAN_POINT('',(8.04382059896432,-35.1624428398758,44.331638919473));
#905=CARTESIAN_POINT('',(8.19687058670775,-34.9359309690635,44.4968809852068));
#906=CARTESIAN_POINT('',(8.51735374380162,-34.4794321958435,44.805373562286));
#907=CARTESIAN_POINT('',(8.68474601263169,-34.2494566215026,44.9486835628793));
#908=CARTESIAN_POINT('',(9.03355708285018,-33.7883224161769,45.2147473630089));
#909=CARTESIAN_POINT('',(9.21497547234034,-33.5571638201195,45.3375017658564));
#910=CARTESIAN_POINT('',(9.5914317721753,-33.0956864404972,45.5640349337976));
#911=CARTESIAN_POINT('',(9.7864997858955,-32.8653707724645,45.6677698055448));
#912=CARTESIAN_POINT('',(10.1889814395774,-32.4082820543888,45.8575407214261));
#913=CARTESIAN_POINT('',(10.3963966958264,-32.1815094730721,45.9435744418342));
#914=CARTESIAN_POINT('',(10.9357222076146,-31.6144699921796,46.1411102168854));
#915=CARTESIAN_POINT('',(11.2753377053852,-31.2777703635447,46.2419338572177));
#916=CARTESIAN_POINT('',(11.978376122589,-30.6217654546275,46.4126134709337));
#917=CARTESIAN_POINT('',(12.3418107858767,-30.3024688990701,46.4824540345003));
#918=CARTESIAN_POINT('',(13.0905088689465,-29.6840405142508,46.5968280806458));
#919=CARTESIAN_POINT('',(13.4758180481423,-29.384954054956,46.6413061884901));
#920=CARTESIAN_POINT('',(14.2650968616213,-28.8100959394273,46.7089216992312));
#921=CARTESIAN_POINT('',(14.6690639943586,-28.5343211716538,46.7320619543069));
#922=CARTESIAN_POINT('',(15.5064196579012,-27.999498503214,46.7598841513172));
#923=CARTESIAN_POINT('',(15.9403329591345,-27.7412414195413,46.7639673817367));
#924=CARTESIAN_POINT('',(16.8234491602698,-27.2526731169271,46.7525338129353));
#925=CARTESIAN_POINT('',(17.2726540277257,-27.0223655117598,46.7370144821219));
#926=CARTESIAN_POINT('',(18.1831087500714,-26.5912128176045,46.6846186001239));
#927=CARTESIAN_POINT('',(18.6443426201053,-26.3903307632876,46.6477691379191));
#928=CARTESIAN_POINT('',(19.5761439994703,-26.018766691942,46.548854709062));
#929=CARTESIAN_POINT('',(20.0467087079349,-25.8480757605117,46.4867972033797));
#930=CARTESIAN_POINT('',(20.879814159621,-25.5748002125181,46.3503573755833));
#931=CARTESIAN_POINT('',(21.2412851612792,-25.4656891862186,46.2824684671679));
#932=CARTESIAN_POINT('',(21.9647946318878,-25.2656109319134,46.125849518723));
#933=CARTESIAN_POINT('',(22.326833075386,-25.1746429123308,46.0371203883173));
#934=CARTESIAN_POINT('',(23.0479388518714,-25.0109668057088,45.8358492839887));
#935=CARTESIAN_POINT('',(23.4070094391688,-24.9382351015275,45.7233384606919));
#936=CARTESIAN_POINT('',(24.1188549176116,-24.8105624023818,45.4714698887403));
#937=CARTESIAN_POINT('',(24.471631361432,-24.755616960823,45.3321188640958));
#938=CARTESIAN_POINT('',(25.1009857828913,-24.6714549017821,45.0531347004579));
#939=CARTESIAN_POINT('',(25.3793967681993,-24.6393411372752,44.9185019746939));
#940=CARTESIAN_POINT('',(25.9265253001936,-24.5855801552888,44.629009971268));
#941=CARTESIAN_POINT('',(26.1952449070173,-24.5639307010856,44.4741550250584));
#942=CARTESIAN_POINT('',(26.7198900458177,-24.5301461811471,44.1439784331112));
#943=CARTESIAN_POINT('',(26.9758341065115,-24.5179969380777,43.9686877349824));
#944=CARTESIAN_POINT('',(27.4725234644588,-24.5019339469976,43.59758081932));
#945=CARTESIAN_POINT('',(27.7132762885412,-24.4980160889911,43.4017748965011));
#946=CARTESIAN_POINT('',(28.1090728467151,-24.4971100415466,43.0505610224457));
#947=CARTESIAN_POINT('',(28.2685572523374,-24.4984274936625,42.9001311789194));
#948=CARTESIAN_POINT('',(28.5777746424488,-24.5038795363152,42.5897862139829));
#949=CARTESIAN_POINT('',(28.7275132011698,-24.508012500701,42.4298766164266));
#950=CARTESIAN_POINT('',(28.8720321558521,-24.5132703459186,42.265370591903));
#951=B_SPLINE_CURVE_WITH_KNOTS('',3,(#895,#896,#897,#898,#899,#900,#901,#902,#903,#904,#905,
#906,#907,#908,#909,#910,#911,#912,#913,#914,#915,#916,#917,#918,#919,#920,#921,#922,#923,#924,
#925,#926,#927,#928,#929,#930,#931,#932,#933,#934,#935,#936,#937,#938,#939,#940,#941,#942,#943,
#944,#945,#946,#947,#948,#949,#950),.UNSPECIFIED.,.F.,.F.,(4,2,2,2,2,2,2,2,2,2,2,2,2,2,2,2,2,2,
2,2,2,2,2,2,2,2,2,4),(0.,0.483826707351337,0.967622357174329,1.93415776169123,2.89115545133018,
3.84829000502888,4.80278053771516,5.75724305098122,6.71388128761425,7.67064502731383,
9.13463558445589,10.599353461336,12.0672571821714,13.5349646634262,15.0484857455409,
16.5622023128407,18.0740006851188,19.5853519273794,20.7353824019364,21.8853626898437,
23.0338458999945,24.1820417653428,25.1138944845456,26.0455479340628,26.9758083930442,
27.9056042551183,28.5629077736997,29.2198319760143),.UNSPECIFIED.);
#952=EDGE_CURVE('E205',#892,#304,#951,.T.);
#953=ORIENTED_EDGE('',*,*,#952,.T.);
#954=EDGE_LOOP('',(#306,#307,#334,#395,#418,#419,#446,#507,#530,#531,#558,#619,#642,#643,#670,
#731,#754,#755,#782,#843,#866,#867,#894,#953));
#955=FACE_BOUND('',#954,.T.);
#956=ORIENTED_EDGE('',*,*,#261,.F.);
#957=EDGE_LOOP('',(#956));
#958=FACE_BOUND('',#957,.T.);
#959=ADVANCED_FACE('F195',(#955,#958),#281,.T.);
#960=CARTESIAN_POINT('',(0.,15.5,25.));
#961=DIRECTION('',(0.,0.,1.));
#962=DIRECTION('',(-1.,0.,0.));
#963=AXIS2_PLACEMENT_3D('',#960,#961,#962);
#964=PLANE('',#963);
#965=ORIENTED_EDGE('',*,*,#33,.F.);
#966=CARTESIAN_POINT('',(29.053463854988,-19.5165631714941,25.));
#967=DIRECTION('',(0.,0.,1.));
#968=DIRECTION('',(-1.,0.,0.));
#969=AXIS2_PLACEMENT_3D('',#966,#967,#968);
#970=CIRCLE('',#969,5.);
#971=CARTESIAN_POINT('',(28.8718321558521,-24.5132630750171,25.));
#972=VERTEX_POINT('',#971);
#973=EDGE_CURVE('E9',#30,#972,#970,.F.);
#974=ORIENTED_EDGE('',*,*,#973,.T.);
#975=CARTESIAN_POINT('',(28.,-48.4974226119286,25.));
#976=DIRECTION('',(0.,0.,1.));
#977=DIRECTION('',(-1.,0.,0.));
#978=AXIS2_PLACEMENT_3D('',#975,#976,#977);
#979=CIRCLE('',#978,24.);
#980=CARTESIAN_POINT('',(6.79319247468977,-37.2603716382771,25.));
#981=VERTEX_POINT('',#980);
#982=EDGE_CURVE('E22',#981,#972,#979,.F.);
#983=ORIENTED_EDGE('',*,*,#982,.F.);
#984=CARTESIAN_POINT('',(2.37510757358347,-34.9193193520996,25.));
#985=DIRECTION('',(0.,0.,1.));
#986=DIRECTION('',(-1.,0.,0.));
#987=AXIS2_PLACEMENT_3D('',#984,#985,#986);
#988=CIRCLE('',#987,5.);
#989=EDGE_CURVE('E515',#981,#64,#988,.F.);
#990=ORIENTED_EDGE('',*,*,#989,.T.);
#991=ORIENTED_EDGE('',*,*,#65,.F.);
#992=CARTESIAN_POINT('',(-2.37510757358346,-34.9193193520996,25.));
#993=DIRECTION('',(0.,0.,1.));
#994=DIRECTION('',(-1.,0.,0.));
#995=AXIS2_PLACEMENT_3D('',#992,#993,#994);
#996=CIRCLE('',#995,5.);
#997=CARTESIAN_POINT('',(-6.79319247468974,-37.2603716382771,25.));
#998=VERTEX_POINT('',#997);
#999=EDGE_CURVE('E512',#62,#998,#996,.F.);
#1000=ORIENTED_EDGE('',*,*,#999,.T.);
#1001=CARTESIAN_POINT('',(-28.,-48.4974226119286,25.));
#1002=DIRECTION('',(0.,0.,1.));
#1003=DIRECTION('',(-1.,0.,0.));
#1004=AXIS2_PLACEMENT_3D('',#1001,#1002,#1003);
#1005=CIRCLE('',#1004,24.);
#1006=CARTESIAN_POINT('',(-28.8718321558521,-24.5132630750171,25.));
#1007=VERTEX_POINT('',#1006);
#1008=EDGE_CURVE('E510',#1007,#998,#1005,.F.);
#1009=ORIENTED_EDGE('',*,*,#1008,.F.);
#1010=CARTESIAN_POINT('',(-29.0534638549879,-19.5165631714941,25.));
#1011=DIRECTION('',(0.,0.,1.));
#1012=DIRECTION('',(-1.,0.,0.));
#1013=AXIS2_PLACEMENT_3D('',#1010,#1011,#1012);
#1014=CIRCLE('',#1013,5.);
#1015=EDGE_CURVE('E507',#1007,#91,#1014,.F.);
#1016=ORIENTED_EDGE('',*,*,#1015,.T.);
#1017=ORIENTED_EDGE('',*,*,#92,.F.);
#1018=CARTESIAN_POINT('',(-31.4285714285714,-15.4027561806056,25.));
#1019=DIRECTION('',(0.,0.,1.));
#1020=DIRECTION('',(-1.,0.,0.));
#1021=AXIS2_PLACEMENT_3D('',#1018,#1019,#1020);
#1022=CIRCLE('',#1021,5.);
#1023=CARTESIAN_POINT('',(-35.6650246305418,-12.74710856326,25.));
#1024=VERTEX_POINT('',#1023);
#1025=EDGE_CURVE('E504',#89,#1024,#1022,.F.);
#1026=ORIENTED_EDGE('',*,*,#1025,.T.);
#1027=CARTESIAN_POINT('',(-56.,0.,25.));
#1028=DIRECTION('',(0.,0.,1.));
#1029=DIRECTION('',(-1.,0.,0.));
#1030=AXIS2_PLACEMENT_3D('',#1027,#1028,#1029);
#1031=CIRCLE('',#1030,24.);
#1032=CARTESIAN_POINT('',(-35.6650246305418,12.7471085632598,25.));
#1033=VERTEX_POINT('',#1032);
#1034=EDGE_CURVE('E502',#1033,#1024,#1031,.F.);
#1035=ORIENTED_EDGE('',*,*,#1034,.F.);
#1036=CARTESIAN_POINT('',(-31.4285714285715,15.4027561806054,25.));
#1037=DIRECTION('',(0.,0.,1.));
#1038=DIRECTION('',(-1.,0.,0.));
#1039=AXIS2_PLACEMENT_3D('',#1036,#1037,#1038);
#1040=CIRCLE('',#1039,5.);
#1041=EDGE_CURVE('E500',#1033,#118,#1040,.F.);
#1042=ORIENTED_EDGE('',*,*,#1041,.T.);
#1043=ORIENTED_EDGE('',*,*,#119,.F.);
#1044=CARTESIAN_POINT('',(-29.0534638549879,19.5165631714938,25.));
#1045=DIRECTION('',(0.,0.,1.));
#1046=DIRECTION('',(-1.,0.,0.));
#1047=AXIS2_PLACEMENT_3D('',#1044,#1045,#1046);
#1048=CIRCLE('',#1047,5.);
#1049=CARTESIAN_POINT('',(-28.8718321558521,24.5132630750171,25.));
#1050=VERTEX_POINT('',#1049);
#1051=EDGE_CURVE('E497',#116,#1050,#1048,.F.);
#1052=ORIENTED_EDGE('',*,*,#1051,.T.);
#1053=CARTESIAN_POINT('',(-28.,48.4974226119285,25.));
#1054=DIRECTION('',(0.,0.,1.));
#1055=DIRECTION('',(-1.,0.,0.));
#1056=AXIS2_PLACEMENT_3D('',#1053,#1054,#1055);
#1057=CIRCLE('',#1056,24.);
#1058=CARTESIAN_POINT('',(-6.79319247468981,37.2603716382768,25.));
#1059=VERTEX_POINT('',#1058);
#1060=EDGE_CURVE('E495',#1059,#1050,#1057,.F.);
#1061=ORIENTED_EDGE('',*,*,#1060,.F.);
#1062=CARTESIAN_POINT('',(-2.37510757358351,34.9193193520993,25.));
#1063=DIRECTION('',(0.,0.,1.));
#1064=DIRECTION('',(-1.,0.,0.));
#1065=AXIS2_PLACEMENT_3D('',#1062,#1063,#1064);
#1066=CIRCLE('',#1065,5.);
#1067=EDGE_CURVE('E492',#1059,#145,#1066,.F.);
#1068=ORIENTED_EDGE('',*,*,#1067,.T.);
#1069=ORIENTED_EDGE('',*,*,#146,.F.);
#1070=CARTESIAN_POINT('',(2.37510757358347,34.9193193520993,25.));
#1071=DIRECTION('',(0.,0.,1.));
#1072=DIRECTION('',(-1.,0.,0.));
#1073=AXIS2_PLACEMENT_3D('',#1070,#1071,#1072);
#1074=CIRCLE('',#1073,5.);
#1075=CARTESIAN_POINT('',(6.79319247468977,37.2603716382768,25.));
#1076=VERTEX_POINT('',#1075);
#1077=EDGE_CURVE('E489',#143,#1076,#1074,.F.);
#1078=ORIENTED_EDGE('',*,*,#1077,.T.);
#1079=CARTESIAN_POINT('',(28.,48.4974226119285,25.));
#1080=DIRECTION('',(0.,0.,1.));
#1081=DIRECTION('',(-1.,0.,0.));
#1082=AXIS2_PLACEMENT_3D('',#1079,#1080,#1081);
#1083=CIRCLE('',#1082,24.);
#1084=CARTESIAN_POINT('',(28.8718321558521,24.5132630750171,25.));
#1085=VERTEX_POINT('',#1084);
#1086=EDGE_CURVE('E487',#1085,#1076,#1083,.F.);
#1087=ORIENTED_EDGE('',*,*,#1086,.F.);
#1088=CARTESIAN_POINT('',(29.0534638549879,19.5165631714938,25.));
#1089=DIRECTION('',(0.,0.,1.));
#1090=DIRECTION('',(-1.,0.,0.));
#1091=AXIS2_PLACEMENT_3D('',#1088,#1089,#1090);
#1092=CIRCLE('',#1091,5.);
#1093=EDGE_CURVE('E485',#1085,#172,#1092,.F.);
#1094=ORIENTED_EDGE('',*,*,#1093,.T.);
#1095=ORIENTED_EDGE('',*,*,#173,.F.);
#1096=CARTESIAN_POINT('',(31.4285714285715,15.4027561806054,25.));
#1097=DIRECTION('',(0.,0.,1.));
#1098=DIRECTION('',(-1.,0.,0.));
#1099=AXIS2_PLACEMENT_3D('',#1096,#1097,#1098);
#1100=CIRCLE('',#1099,5.);
#1101=CARTESIAN_POINT('',(35.6650246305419,12.7471085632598,25.));
#1102=VERTEX_POINT('',#1101);
#1103=EDGE_CURVE('E482',#170,#1102,#1100,.F.);
#1104=ORIENTED_EDGE('',*,*,#1103,.T.);
#1105=CARTESIAN_POINT('',(56.,0.,25.));
#1106=DIRECTION('',(0.,0.,1.));
#1107=DIRECTION('',(-1.,0.,0.));
#1108=AXIS2_PLACEMENT_3D('',#1105,#1106,#1107);
#1109=CIRCLE('',#1108,24.);
#1110=CARTESIAN_POINT('',(35.6650246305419,-12.7471085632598,25.));
#1111=VERTEX_POINT('',#1110);
#1112=EDGE_CURVE('E480',#1111,#1102,#1109,.F.);
#1113=ORIENTED_EDGE('',*,*,#1112,.F.);
#1114=CARTESIAN_POINT('',(31.4285714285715,-15.4027561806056,25.));
#1115=DIRECTION('',(0.,0.,1.));
#1116=DIRECTION('',(-1.,0.,0.));
#1117=AXIS2_PLACEMENT_3D('',#1114,#1115,#1116);
#1118=CIRCLE('',#1117,5.);
#1119=EDGE_CURVE('E189',#1111,#32,#1118,.F.);
#1120=ORIENTED_EDGE('',*,*,#1119,.T.);
#1121=EDGE_LOOP('',(#965,#974,#983,#990,#991,#1000,#1009,#1016,#1017,#1026,#1035,#1042,#1043,
#1052,#1061,#1068,#1069,#1078,#1087,#1094,#1095,#1104,#1113,#1120));
#1122=FACE_BOUND('',#1121,.T.);
#1123=CARTESIAN_POINT('',(0.,0.,25.));
#1124=DIRECTION('',(0.,0.,1.));
#1125=DIRECTION('',(-1.,0.,0.));
#1126=AXIS2_PLACEMENT_3D('',#1123,#1124,#1125);
#1127=CIRCLE('',#1126,15.5);
#1128=CARTESIAN_POINT('',(-15.5,0.,25.));
#1129=VERTEX_POINT('',#1128);
#1130=EDGE_CURVE('E468',#1129,#1129,#1127,.T.);
#1131=ORIENTED_EDGE('',*,*,#1130,.T.);
#1132=EDGE_LOOP('',(#1131));
#1133=FACE_BOUND('',#1132,.T.);
#1134=ADVANCED_FACE('F418',(#1122,#1133),#964,.F.);
#1135=CARTESIAN_POINT('',(0.,0.,64.59576815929));
#1136=DIRECTION('',(0.,0.,1.));
#1137=DIRECTION('',(-1.,0.,0.));
#1138=AXIS2_PLACEMENT_3D('',#1135,#1136,#1137);
#1139=CYLINDRICAL_SURFACE('',#1138,15.5);
#1140=CARTESIAN_POINT('',(0.,0.,23.));
#1141=DIRECTION('',(0.,0.,1.));
#1142=DIRECTION('',(-1.,0.,0.));
#1143=AXIS2_PLACEMENT_3D('',#1140,#1141,#1142);
#1144=CIRCLE('',#1143,15.5);
#1145=CARTESIAN_POINT('',(-15.5,0.,23.));
#1146=VERTEX_POINT('',#1145);
#1147=EDGE_CURVE('E850',#1146,#1146,#1144,.T.);
#1148=ORIENTED_EDGE('',*,*,#1147,.T.);
#1149=EDGE_LOOP('',(#1148));
#1150=FACE_BOUND('',#1149,.T.);
#1151=ORIENTED_EDGE('',*,*,#1130,.F.);
#1152=EDGE_LOOP('',(#1151));
#1153=FACE_BOUND('',#1152,.T.);
#1154=ADVANCED_FACE('F414',(#1150,#1153),#1139,.T.);
#1155=CARTESIAN_POINT('',(0.,12.5,23.));
#1156=DIRECTION('',(0.,0.,1.));
#1157=DIRECTION('',(-1.,0.,0.));
#1158=AXIS2_PLACEMENT_3D('',#1155,#1156,#1157);
#1159=PLANE('',#1158);
#1160=ORIENTED_EDGE('',*,*,#1147,.F.);
#1161=EDGE_LOOP('',(#1160));
#1162=FACE_BOUND('',#1161,.T.);
#1163=CARTESIAN_POINT('',(0.,0.,23.));
#1164=DIRECTION('',(0.,0.,1.));
#1165=DIRECTION('',(-1.,0.,0.));
#1166=AXIS2_PLACEMENT_3D('',#1163,#1164,#1165);
#1167=CIRCLE('',#1166,12.5);
#1168=CARTESIAN_POINT('',(-12.5,0.,23.));
#1169=VERTEX_POINT('',#1168);
#1170=EDGE_CURVE('E853',#1169,#1169,#1167,.T.);
#1171=ORIENTED_EDGE('',*,*,#1170,.T.);
#1172=EDGE_LOOP('',(#1171));
#1173=FACE_BOUND('',#1172,.T.);
#1174=ADVANCED_FACE('F410',(#1162,#1173),#1159,.F.);
#1175=CARTESIAN_POINT('',(0.,0.,64.59576815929));
#1176=DIRECTION('',(0.,0.,1.));
#1177=DIRECTION('',(-1.,0.,0.));
#1178=AXIS2_PLACEMENT_3D('',#1175,#1176,#1177);
#1179=CYLINDRICAL_SURFACE('',#1178,12.5);
#1180=ORIENTED_EDGE('',*,*,#208,.T.);
#1181=EDGE_LOOP('',(#1180));
#1182=FACE_BOUND('',#1181,.T.);
#1183=ORIENTED_EDGE('',*,*,#1170,.F.);
#1184=EDGE_LOOP('',(#1183));
#1185=FACE_BOUND('',#1184,.T.);
#1186=ADVANCED_FACE('F404',(#1182,#1185),#1179,.T.);
#1187=CARTESIAN_POINT('',(0.,0.,49.));
#1188=DIRECTION('',(0.,0.,1.));
#1189=DIRECTION('',(-1.,0.,0.));
#1190=AXIS2_PLACEMENT_3D('',#1187,#1188,#1189);
#1191=CYLINDRICAL_SURFACE('',#1190,20.);
#1192=CARTESIAN_POINT('',(0.,0.,49.));
#1193=DIRECTION('',(0.,0.,1.));
#1194=DIRECTION('',(-1.,0.,0.));
#1195=AXIS2_PLACEMENT_3D('',#1192,#1193,#1194);
#1196=CIRCLE('',#1195,20.);
#1197=CARTESIAN_POINT('',(-20.,0.,49.));
#1198=VERTEX_POINT('',#1197);
#1199=EDGE_CURVE('E203',#1198,#1198,#1196,.T.);
#1200=ORIENTED_EDGE('',*,*,#1199,.F.);
#1201=EDGE_LOOP('',(#1200));
#1202=FACE_BOUND('',#1201,.T.);
#1203=ORIENTED_EDGE('',*,*,#272,.T.);
#1204=EDGE_LOOP('',(#1203));
#1205=FACE_BOUND('',#1204,.T.);
#1206=ADVANCED_FACE('F235',(#1202,#1205),#1191,.F.);
#1207=CARTESIAN_POINT('',(0.,0.,49.));
#1208=DIRECTION('',(0.,0.,1.));
#1209=DIRECTION('',(-1.,0.,0.));
#1210=AXIS2_PLACEMENT_3D('',#1207,#1208,#1209);
#1211=PLANE('',#1210);
#1212=ORIENTED_EDGE('',*,*,#1199,.T.);
#1213=EDGE_LOOP('',(#1212));
#1214=FACE_BOUND('',#1213,.T.);
#1215=ADVANCED_FACE('F234',(#1214),#1211,.T.);
#1216=CARTESIAN_POINT('',(56.,0.,0.));
#1217=DIRECTION('',(0.,0.,1.));
#1218=DIRECTION('',(-1.,0.,0.));
#1219=AXIS2_PLACEMENT_3D('',#1216,#1217,#1218);
#1220=CYLINDRICAL_SURFACE('',#1219,24.);
#1221=DIRECTION('',(0.,0.,1.));
#1222=VECTOR('',#1221,1.);
#1223=CARTESIAN_POINT('',(35.6650246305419,-12.7471085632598,0.));
#1224=LINE('',#1223,#1222);
#1225=EDGE_CURVE('E29',#1111,#332,#1224,.T.);
#1226=ORIENTED_EDGE('',*,*,#1225,.F.);
#1227=ORIENTED_EDGE('',*,*,#1112,.T.);
#1228=DIRECTION('',(0.,0.,1.));
#1229=VECTOR('',#1228,1.);
#1230=CARTESIAN_POINT('',(35.6650246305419,12.7471085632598,0.));
#1231=LINE('',#1230,#1229);
#1232=EDGE_CURVE('E177',#1102,#393,#1231,.T.);
#1233=ORIENTED_EDGE('',*,*,#1232,.T.);
#1234=ORIENTED_EDGE('',*,*,#394,.F.);
#1235=EDGE_LOOP('',(#1226,#1227,#1233,#1234));
#1236=FACE_BOUND('',#1235,.T.);
#1237=ADVANCED_FACE('F175',(#1236),#1220,.F.);
#1238=CARTESIAN_POINT('',(31.4285714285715,15.4027561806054,0.));
#1239=DIRECTION('',(0.,0.,1.));
#1240=DIRECTION('',(-1.,0.,0.));
#1241=AXIS2_PLACEMENT_3D('',#1238,#1239,#1240);
#1242=CYLINDRICAL_SURFACE('',#1241,5.);
#1243=ORIENTED_EDGE('',*,*,#417,.T.);
#1244=ORIENTED_EDGE('',*,*,#1232,.F.);
#1245=ORIENTED_EDGE('',*,*,#1103,.F.);
#1246=ORIENTED_EDGE('',*,*,#191,.T.);
#1247=EDGE_LOOP('',(#1243,#1244,#1245,#1246));
#1248=FACE_BOUND('',#1247,.T.);
#1249=ADVANCED_FACE('F228',(#1248),#1242,.T.);
#1250=CARTESIAN_POINT('',(31.4285714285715,-15.4027561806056,0.));
#1251=DIRECTION('',(0.,0.,1.));
#1252=DIRECTION('',(-1.,0.,0.));
#1253=AXIS2_PLACEMENT_3D('',#1250,#1251,#1252);
#1254=CYLINDRICAL_SURFACE('',#1253,5.);
#1255=ORIENTED_EDGE('',*,*,#333,.T.);
#1256=ORIENTED_EDGE('',*,*,#41,.F.);
#1257=ORIENTED_EDGE('',*,*,#1119,.F.);
#1258=ORIENTED_EDGE('',*,*,#1225,.T.);
#1259=EDGE_LOOP('',(#1255,#1256,#1257,#1258));
#1260=FACE_BOUND('',#1259,.T.);
#1261=ADVANCED_FACE('F185',(#1260),#1254,.T.);
#1262=CARTESIAN_POINT('',(29.0534638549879,19.5165631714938,0.));
#1263=DIRECTION('',(0.,0.,1.));
#1264=DIRECTION('',(-1.,0.,0.));
#1265=AXIS2_PLACEMENT_3D('',#1262,#1263,#1264);
#1266=CYLINDRICAL_SURFACE('',#1265,5.);
#1267=ORIENTED_EDGE('',*,*,#445,.T.);
#1268=ORIENTED_EDGE('',*,*,#181,.F.);
#1269=ORIENTED_EDGE('',*,*,#1093,.F.);
#1270=DIRECTION('',(0.,0.,1.));
#1271=VECTOR('',#1270,1.);
#1272=CARTESIAN_POINT('',(28.8718321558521,24.5132630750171,0.));
#1273=LINE('',#1272,#1271);
#1274=EDGE_CURVE('E571',#1085,#444,#1273,.T.);
#1275=ORIENTED_EDGE('',*,*,#1274,.T.);
#1276=EDGE_LOOP('',(#1267,#1268,#1269,#1275));
#1277=FACE_BOUND('',#1276,.T.);
#1278=ADVANCED_FACE('F227',(#1277),#1266,.T.);
#1279=CARTESIAN_POINT('',(28.,48.4974226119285,0.));
#1280=DIRECTION('',(0.,0.,1.));
#1281=DIRECTION('',(-1.,0.,0.));
#1282=AXIS2_PLACEMENT_3D('',#1279,#1280,#1281);
#1283=CYLINDRICAL_SURFACE('',#1282,24.);
#1284=ORIENTED_EDGE('',*,*,#1274,.F.);
#1285=ORIENTED_EDGE('',*,*,#1086,.T.);
#1286=DIRECTION('',(0.,0.,1.));
#1287=VECTOR('',#1286,1.);
#1288=CARTESIAN_POINT('',(6.79319247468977,37.2603716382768,0.));
#1289=LINE('',#1288,#1287);
#1290=EDGE_CURVE('E568',#1076,#505,#1289,.T.);
#1291=ORIENTED_EDGE('',*,*,#1290,.T.);
#1292=ORIENTED_EDGE('',*,*,#506,.F.);
#1293=EDGE_LOOP('',(#1284,#1285,#1291,#1292));
#1294=FACE_BOUND('',#1293,.T.);
#1295=ADVANCED_FACE('F265',(#1294),#1283,.F.);
#1296=CARTESIAN_POINT('',(2.37510757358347,34.9193193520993,0.));
#1297=DIRECTION('',(0.,0.,1.));
#1298=DIRECTION('',(-1.,0.,0.));
#1299=AXIS2_PLACEMENT_3D('',#1296,#1297,#1298);
#1300=CYLINDRICAL_SURFACE('',#1299,5.);
#1301=ORIENTED_EDGE('',*,*,#529,.T.);
#1302=ORIENTED_EDGE('',*,*,#1290,.F.);
#1303=ORIENTED_EDGE('',*,*,#1077,.F.);
#1304=ORIENTED_EDGE('',*,*,#164,.T.);
#1305=EDGE_LOOP('',(#1301,#1302,#1303,#1304));
#1306=FACE_BOUND('',#1305,.T.);
#1307=ADVANCED_FACE('F270',(#1306),#1300,.T.);
#1308=CARTESIAN_POINT('',(-2.37510757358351,34.9193193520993,0.));
#1309=DIRECTION('',(0.,0.,1.));
#1310=DIRECTION('',(-1.,0.,0.));
#1311=AXIS2_PLACEMENT_3D('',#1308,#1309,#1310);
#1312=CYLINDRICAL_SURFACE('',#1311,5.);
#1313=ORIENTED_EDGE('',*,*,#557,.T.);
#1314=ORIENTED_EDGE('',*,*,#154,.F.);
#1315=ORIENTED_EDGE('',*,*,#1067,.F.);
#1316=DIRECTION('',(0.,0.,1.));
#1317=VECTOR('',#1316,1.);
#1318=CARTESIAN_POINT('',(-6.79319247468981,37.2603716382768,0.));
#1319=LINE('',#1318,#1317);
#1320=EDGE_CURVE('E560',#1059,#556,#1319,.T.);
#1321=ORIENTED_EDGE('',*,*,#1320,.T.);
#1322=EDGE_LOOP('',(#1313,#1314,#1315,#1321));
#1323=FACE_BOUND('',#1322,.T.);
#1324=ADVANCED_FACE('F275',(#1323),#1312,.T.);
#1325=CARTESIAN_POINT('',(-28.,48.4974226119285,0.));
#1326=DIRECTION('',(0.,0.,1.));
#1327=DIRECTION('',(-1.,0.,0.));
#1328=AXIS2_PLACEMENT_3D('',#1325,#1326,#1327);
#1329=CYLINDRICAL_SURFACE('',#1328,24.);
#1330=ORIENTED_EDGE('',*,*,#1320,.F.);
#1331=ORIENTED_EDGE('',*,*,#1060,.T.);
#1332=DIRECTION('',(0.,0.,1.));
#1333=VECTOR('',#1332,1.);
#1334=CARTESIAN_POINT('',(-28.8718321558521,24.5132630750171,0.));
#1335=LINE('',#1334,#1333);
#1336=EDGE_CURVE('E557',#1050,#617,#1335,.T.);
#1337=ORIENTED_EDGE('',*,*,#1336,.T.);
#1338=ORIENTED_EDGE('',*,*,#618,.F.);
#1339=EDGE_LOOP('',(#1330,#1331,#1337,#1338));
#1340=FACE_BOUND('',#1339,.T.);
#1341=ADVANCED_FACE('F305',(#1340),#1329,.F.);
#1342=CARTESIAN_POINT('',(-29.0534638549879,19.5165631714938,0.));
#1343=DIRECTION('',(0.,0.,1.));
#1344=DIRECTION('',(-1.,0.,0.));
#1345=AXIS2_PLACEMENT_3D('',#1342,#1343,#1344);
#1346=CYLINDRICAL_SURFACE('',#1345,5.);
#1347=ORIENTED_EDGE('',*,*,#641,.T.);
#1348=ORIENTED_EDGE('',*,*,#1336,.F.);
#1349=ORIENTED_EDGE('',*,*,#1051,.F.);
#1350=ORIENTED_EDGE('',*,*,#137,.T.);
#1351=EDGE_LOOP('',(#1347,#1348,#1349,#1350));
#1352=FACE_BOUND('',#1351,.T.);
#1353=ADVANCED_FACE('F308',(#1352),#1346,.T.);
#1354=CARTESIAN_POINT('',(-31.4285714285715,15.4027561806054,0.));
#1355=DIRECTION('',(0.,0.,1.));
#1356=DIRECTION('',(-1.,0.,0.));
#1357=AXIS2_PLACEMENT_3D('',#1354,#1355,#1356);
#1358=CYLINDRICAL_SURFACE('',#1357,5.);
#1359=ORIENTED_EDGE('',*,*,#669,.T.);
#1360=ORIENTED_EDGE('',*,*,#127,.F.);
#1361=ORIENTED_EDGE('',*,*,#1041,.F.);
#1362=DIRECTION('',(0.,0.,1.));
#1363=VECTOR('',#1362,1.);
#1364=CARTESIAN_POINT('',(-35.6650246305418,12.7471085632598,0.));
#1365=LINE('',#1364,#1363);
#1366=EDGE_CURVE('E551',#1033,#668,#1365,.T.);
#1367=ORIENTED_EDGE('',*,*,#1366,.T.);
#1368=EDGE_LOOP('',(#1359,#1360,#1361,#1367));
#1369=FACE_BOUND('',#1368,.T.);
#1370=ADVANCED_FACE('F313',(#1369),#1358,.T.);
#1371=CARTESIAN_POINT('',(-56.,0.,0.));
#1372=DIRECTION('',(0.,0.,1.));
#1373=DIRECTION('',(-1.,0.,0.));
#1374=AXIS2_PLACEMENT_3D('',#1371,#1372,#1373);
#1375=CYLINDRICAL_SURFACE('',#1374,24.);
#1376=ORIENTED_EDGE('',*,*,#1366,.F.);
#1377=ORIENTED_EDGE('',*,*,#1034,.T.);
#1378=DIRECTION('',(0.,0.,1.));
#1379=VECTOR('',#1378,1.);
#1380=CARTESIAN_POINT('',(-35.6650246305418,-12.74710856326,0.));
#1381=LINE('',#1380,#1379);
#1382=EDGE_CURVE('E548',#1024,#729,#1381,.T.);
#1383=ORIENTED_EDGE('',*,*,#1382,.T.);
#1384=ORIENTED_EDGE('',*,*,#730,.F.);
#1385=EDGE_LOOP('',(#1376,#1377,#1383,#1384));
#1386=FACE_BOUND('',#1385,.T.);
#1387=ADVANCED_FACE('F318',(#1386),#1375,.F.);
#1388=CARTESIAN_POINT('',(-31.4285714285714,-15.4027561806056,0.));
#1389=DIRECTION('',(0.,0.,1.));
#1390=DIRECTION('',(-1.,0.,0.));
#1391=AXIS2_PLACEMENT_3D('',#1388,#1389,#1390);
#1392=CYLINDRICAL_SURFACE('',#1391,5.);
#1393=ORIENTED_EDGE('',*,*,#753,.T.);
#1394=ORIENTED_EDGE('',*,*,#1382,.F.);
#1395=ORIENTED_EDGE('',*,*,#1025,.F.);
#1396=ORIENTED_EDGE('',*,*,#110,.T.);
#1397=EDGE_LOOP('',(#1393,#1394,#1395,#1396));
#1398=FACE_BOUND('',#1397,.T.);
#1399=ADVANCED_FACE('F347',(#1398),#1392,.T.);
#1400=CARTESIAN_POINT('',(-29.0534638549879,-19.5165631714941,0.));
#1401=DIRECTION('',(0.,0.,1.));
#1402=DIRECTION('',(-1.,0.,0.));
#1403=AXIS2_PLACEMENT_3D('',#1400,#1401,#1402);
#1404=CYLINDRICAL_SURFACE('',#1403,5.);
#1405=ORIENTED_EDGE('',*,*,#781,.T.);
#1406=ORIENTED_EDGE('',*,*,#100,.F.);
#1407=ORIENTED_EDGE('',*,*,#1015,.F.);
#1408=DIRECTION('',(0.,0.,1.));
#1409=VECTOR('',#1408,1.);
#1410=CARTESIAN_POINT('',(-28.8718321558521,-24.5132630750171,0.));
#1411=LINE('',#1410,#1409);
#1412=EDGE_CURVE('E540',#1007,#780,#1411,.T.);
#1413=ORIENTED_EDGE('',*,*,#1412,.T.);
#1414=EDGE_LOOP('',(#1405,#1406,#1407,#1413));
#1415=FACE_BOUND('',#1414,.T.);
#1416=ADVANCED_FACE('F350',(#1415),#1404,.T.);
#1417=CARTESIAN_POINT('',(-28.,-48.4974226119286,0.));
#1418=DIRECTION('',(0.,0.,1.));
#1419=DIRECTION('',(-1.,0.,0.));
#1420=AXIS2_PLACEMENT_3D('',#1417,#1418,#1419);
#1421=CYLINDRICAL_SURFACE('',#1420,24.);
#1422=ORIENTED_EDGE('',*,*,#1412,.F.);
#1423=ORIENTED_EDGE('',*,*,#1008,.T.);
#1424=DIRECTION('',(0.,0.,1.));
#1425=VECTOR('',#1424,1.);
#1426=CARTESIAN_POINT('',(-6.79319247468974,-37.2603716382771,0.));
#1427=LINE('',#1426,#1425);
#1428=EDGE_CURVE('E537',#998,#841,#1427,.T.);
#1429=ORIENTED_EDGE('',*,*,#1428,.T.);
#1430=ORIENTED_EDGE('',*,*,#842,.F.);
#1431=EDGE_LOOP('',(#1422,#1423,#1429,#1430));
#1432=FACE_BOUND('',#1431,.T.);
#1433=ADVANCED_FACE('F355',(#1432),#1421,.F.);
#1434=CARTESIAN_POINT('',(-2.37510757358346,-34.9193193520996,0.));
#1435=DIRECTION('',(0.,0.,1.));
#1436=DIRECTION('',(-1.,0.,0.));
#1437=AXIS2_PLACEMENT_3D('',#1434,#1435,#1436);
#1438=CYLINDRICAL_SURFACE('',#1437,5.);
#1439=ORIENTED_EDGE('',*,*,#865,.T.);
#1440=ORIENTED_EDGE('',*,*,#1428,.F.);
#1441=ORIENTED_EDGE('',*,*,#999,.F.);
#1442=ORIENTED_EDGE('',*,*,#83,.T.);
#1443=EDGE_LOOP('',(#1439,#1440,#1441,#1442));
#1444=FACE_BOUND('',#1443,.T.);
#1445=ADVANCED_FACE('F360',(#1444),#1438,.T.);
#1446=CARTESIAN_POINT('',(29.053463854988,-19.5165631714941,0.));
#1447=DIRECTION('',(0.,0.,1.));
#1448=DIRECTION('',(-1.,0.,0.));
#1449=AXIS2_PLACEMENT_3D('',#1446,#1447,#1448);
#1450=CYLINDRICAL_SURFACE('',#1449,5.);
#1451=ORIENTED_EDGE('',*,*,#305,.T.);
#1452=DIRECTION('',(0.,0.,1.));
#1453=VECTOR('',#1452,1.);
#1454=CARTESIAN_POINT('',(28.8718321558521,-24.5132630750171,0.));
#1455=LINE('',#1454,#1453);
#1456=EDGE_CURVE('E521',#972,#304,#1455,.T.);
#1457=ORIENTED_EDGE('',*,*,#1456,.F.);
#1458=ORIENTED_EDGE('',*,*,#973,.F.);
#1459=ORIENTED_EDGE('',*,*,#56,.T.);
#1460=EDGE_LOOP('',(#1451,#1457,#1458,#1459));
#1461=FACE_BOUND('',#1460,.T.);
#1462=ADVANCED_FACE('F395',(#1461),#1450,.T.);
#1463=CARTESIAN_POINT('',(28.,-48.4974226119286,0.));
#1464=DIRECTION('',(0.,0.,1.));
#1465=DIRECTION('',(-1.,0.,0.));
#1466=AXIS2_PLACEMENT_3D('',#1463,#1464,#1465);
#1467=CYLINDRICAL_SURFACE('',#1466,24.);
#1468=DIRECTION('',(0.,0.,1.));
#1469=VECTOR('',#1468,1.);
#1470=CARTESIAN_POINT('',(6.79319247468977,-37.2603716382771,0.));
#1471=LINE('',#1470,#1469);
#1472=EDGE_CURVE('E524',#981,#892,#1471,.T.);
#1473=ORIENTED_EDGE('',*,*,#1472,.F.);
#1474=ORIENTED_EDGE('',*,*,#982,.T.);
#1475=ORIENTED_EDGE('',*,*,#1456,.T.);
#1476=ORIENTED_EDGE('',*,*,#952,.F.);
#1477=EDGE_LOOP('',(#1473,#1474,#1475,#1476));
#1478=FACE_BOUND('',#1477,.T.);
#1479=ADVANCED_FACE('F390',(#1478),#1467,.F.);
#1480=CARTESIAN_POINT('',(2.37510757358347,-34.9193193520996,0.));
#1481=DIRECTION('',(0.,0.,1.));
#1482=DIRECTION('',(-1.,0.,0.));
#1483=AXIS2_PLACEMENT_3D('',#1480,#1481,#1482);
#1484=CYLINDRICAL_SURFACE('',#1483,5.);
#1485=ORIENTED_EDGE('',*,*,#893,.T.);
#1486=ORIENTED_EDGE('',*,*,#73,.F.);
#1487=ORIENTED_EDGE('',*,*,#989,.F.);
#1488=ORIENTED_EDGE('',*,*,#1472,.T.);
#1489=EDGE_LOOP('',(#1485,#1486,#1487,#1488));
#1490=FACE_BOUND('',#1489,.T.);
#1491=ADVANCED_FACE('F387',(#1490),#1484,.T.);
#1492=CARTESIAN_POINT('',(0.,0.,28.));
#1493=DIRECTION('',(0.,0.,-1.));
#1494=DIRECTION('',(1.,0.,0.));
#1495=AXIS2_PLACEMENT_3D('',#1492,#1493,#1494);
#1496=CYLINDRICAL_SURFACE('',#1495,8.);
#1497=CARTESIAN_POINT('',(0.,0.,28.));
#1498=DIRECTION('',(0.,0.,-1.));
#1499=DIRECTION('',(1.,0.,0.));
#1500=AXIS2_PLACEMENT_3D('',#1497,#1498,#1499);
#1501=CIRCLE('',#1500,8.);
#1502=CARTESIAN_POINT('',(8.,0.,28.));
#1503=VERTEX_POINT('',#1502);
#1504=EDGE_CURVE('E191',#1503,#1503,#1501,.T.);
#1505=ORIENTED_EDGE('',*,*,#1504,.F.);
#1506=EDGE_LOOP('',(#1505));
#1507=FACE_BOUND('',#1506,.T.);
#1508=ORIENTED_EDGE('',*,*,#236,.T.);
#1509=EDGE_LOOP('',(#1508));
#1510=FACE_BOUND('',#1509,.T.);
#1511=ADVANCED_FACE('F229',(#1507,#1510),#1496,.F.);
#1512=CARTESIAN_POINT('',(0.,0.,28.));
#1513=DIRECTION('',(0.,0.,-1.));
#1514=DIRECTION('',(1.,0.,0.));
#1515=AXIS2_PLACEMENT_3D('',#1512,#1513,#1514);
#1516=PLANE('',#1515);
#1517=ORIENTED_EDGE('',*,*,#1504,.T.);
#1518=EDGE_LOOP('',(#1517));
#1519=FACE_BOUND('',#1518,.T.);
#1520=ADVANCED_FACE('F392',(#1519),#1516,.T.);
#1521=CLOSED_SHELL('',(#60,#87,#114,#141,#168,#195,#223,#243,#276,#959,#1134,#1154,#1174,#1186,
#1206,#1215,#1237,#1249,#1261,#1278,#1295,#1307,#1324,#1341,#1353,#1370,#1387,#1399,#1416,#1433,
#1445,#1462,#1479,#1491,#1511,#1520));
#1522=MANIFOLD_SOLID_BREP('B1',#1521);
#1523=ADVANCED_BREP_SHAPE_REPRESENTATION('',(#18,#1522),#14);
#1524=SHAPE_DEFINITION_REPRESENTATION(#9,#1523);
ENDSEC;
END-ISO-10303-21;
